VERSION 5.7 ;
  NOWIREEXTENSIONATPIN ON ;
  DIVIDERCHAR "/" ;
  BUSBITCHARS "[]" ;
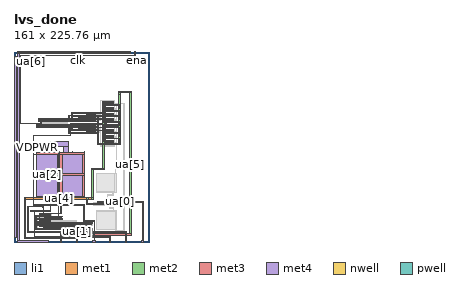
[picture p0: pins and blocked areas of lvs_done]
MACRO lvs_done (1)
  CLASS BLOCK ;
  FOREIGN lvs_done (1) ;
  ORIGIN 0.000 0.000 ;
  SIZE 161.000 BY 225.760 ;
  PIN clk
    DIRECTION INPUT ;
    USE SIGNAL ;
    ANTENNAGATEAREA 0.742500 ;
    PORT
      LAYER li1 ;
        RECT 32.645 144.295 32.980 144.565 ;
        RECT 29.625 137.870 29.955 138.120 ;
      LAYER met1 ;
        RECT 31.805 144.580 32.210 144.610 ;
        RECT 31.805 144.285 32.920 144.580 ;
        RECT 31.805 144.255 32.210 144.285 ;
        RECT 7.135 141.320 7.485 141.350 ;
        RECT 28.670 141.320 29.080 141.350 ;
        RECT 31.800 141.320 32.210 141.350 ;
        RECT 7.135 140.970 32.210 141.320 ;
        RECT 7.135 140.940 7.485 140.970 ;
        RECT 28.670 140.940 29.080 140.970 ;
        RECT 31.800 140.940 32.210 140.970 ;
        RECT 28.700 138.130 29.050 138.160 ;
        RECT 28.700 137.840 29.895 138.130 ;
        RECT 28.700 137.810 29.050 137.840 ;
      LAYER met2 ;
        RECT 7.135 221.565 7.530 221.915 ;
        RECT 7.135 141.320 7.485 221.565 ;
        RECT 31.805 144.255 32.210 144.610 ;
        RECT 31.835 141.350 32.180 144.255 ;
        RECT 7.105 140.970 7.515 141.320 ;
        RECT 28.670 140.940 29.080 141.350 ;
        RECT 31.800 140.940 32.210 141.350 ;
        RECT 28.700 137.810 29.050 140.940 ;
      LAYER met3 ;
        RECT 7.160 221.915 7.510 221.940 ;
        RECT 7.160 221.565 144.115 221.915 ;
        RECT 7.160 221.540 7.510 221.565 ;
      LAYER met4 ;
        RECT 143.740 224.710 144.190 225.765 ;
        RECT 143.740 221.560 144.090 224.710 ;
    END
  END clk
  PIN ena
    DIRECTION INPUT ;
    USE SIGNAL ;
    PORT
      LAYER met4 ;
        RECT 146.590 224.760 146.890 225.760 ;
    END
  END ena
  PIN rst_n
    DIRECTION INPUT ;
    USE SIGNAL ;
    PORT
      LAYER met4 ;
        RECT 141.070 224.760 141.370 225.760 ;
    END
  END rst_n
  PIN ua[0]
    DIRECTION INOUT ;
    USE SIGNAL ;
    ANTENNADIFFAREA 5.117500 ;
    PORT
      LAYER nwell ;
        RECT 106.360 47.870 108.640 47.900 ;
        RECT 98.640 46.280 108.640 47.870 ;
        RECT 113.030 47.890 113.870 47.910 ;
        RECT 115.230 47.890 122.970 47.910 ;
        RECT 113.030 46.305 122.970 47.890 ;
        RECT 113.040 46.300 115.470 46.305 ;
        RECT 98.640 46.265 106.380 46.280 ;
      LAYER li1 ;
        RECT 98.830 47.595 106.190 47.765 ;
        RECT 107.980 47.615 108.440 47.785 ;
        RECT 113.220 47.635 113.680 47.805 ;
        RECT 115.420 47.635 122.780 47.805 ;
        RECT 99.030 46.445 99.240 47.595 ;
        RECT 99.910 46.795 100.080 47.595 ;
        RECT 100.750 46.795 100.920 47.595 ;
        RECT 101.590 46.795 101.760 47.595 ;
        RECT 102.430 46.795 102.600 47.595 ;
        RECT 103.270 46.795 103.440 47.595 ;
        RECT 104.110 46.795 104.280 47.595 ;
        RECT 104.950 46.795 105.120 47.595 ;
        RECT 105.790 46.795 106.000 47.595 ;
        RECT 108.065 46.450 108.355 47.615 ;
        RECT 113.305 46.470 113.595 47.635 ;
        RECT 115.620 46.485 115.830 47.635 ;
        RECT 116.500 46.835 116.670 47.635 ;
        RECT 117.340 46.835 117.510 47.635 ;
        RECT 118.180 46.835 118.350 47.635 ;
        RECT 119.020 46.835 119.190 47.635 ;
        RECT 119.860 46.835 120.030 47.635 ;
        RECT 120.700 46.835 120.870 47.635 ;
        RECT 121.540 46.835 121.710 47.635 ;
        RECT 122.380 46.835 122.590 47.635 ;
      LAYER met1 ;
        RECT 98.780 47.390 153.880 48.390 ;
      LAYER met2 ;
        RECT 152.850 5.100 153.850 48.420 ;
      LAYER met3 ;
        RECT 152.825 5.285 153.875 6.285 ;
        RECT 152.850 0.010 153.850 5.285 ;
      LAYER met4 ;
        RECT 151.540 0.000 154.150 1.340 ;
    END
  END ua[0]
  PIN ua[1]
    DIRECTION INOUT ;
    USE SIGNAL ;
    ANTENNAGATEAREA 3.960000 ;
    PORT
      LAYER li1 ;
        RECT 35.975 31.975 41.415 32.215 ;
      LAYER met1 ;
        RECT 34.660 32.260 35.000 32.600 ;
        RECT 34.660 32.230 35.340 32.260 ;
        RECT 34.660 31.950 38.105 32.230 ;
        RECT 34.660 31.920 35.340 31.950 ;
      LAYER met2 ;
        RECT 16.225 42.235 16.795 42.260 ;
        RECT 16.205 41.715 16.815 42.235 ;
        RECT 16.225 12.345 16.795 41.715 ;
        RECT 33.845 41.690 35.015 42.260 ;
        RECT 34.445 41.090 35.015 41.690 ;
        RECT 34.690 32.600 34.970 41.090 ;
        RECT 34.660 32.260 35.000 32.600 ;
        RECT 34.660 31.920 35.340 32.260 ;
        RECT 16.225 11.775 16.840 12.345 ;
      LAYER met3 ;
        RECT 16.225 41.690 35.015 42.260 ;
        RECT 34.445 41.090 35.015 41.690 ;
        RECT 16.250 12.345 16.820 12.370 ;
        RECT 132.905 12.345 133.475 12.365 ;
        RECT 16.250 11.775 133.475 12.345 ;
        RECT 16.250 11.750 16.820 11.775 ;
        RECT 132.905 11.745 133.475 11.775 ;
      LAYER met4 ;
        RECT 132.900 11.770 133.480 12.340 ;
        RECT 132.905 1.240 133.475 11.770 ;
        RECT 132.390 0.000 133.570 1.240 ;
    END
  END ua[1]
  PIN ua[2]
    DIRECTION INOUT ;
    USE SIGNAL ;
    ANTENNAGATEAREA 7.920000 ;
    PORT
      LAYER li1 ;
        RECT 35.975 21.235 41.415 21.475 ;
        RECT 35.975 16.635 41.415 16.875 ;
      LAYER met1 ;
        RECT 24.375 21.520 24.715 21.860 ;
        RECT 24.375 21.490 25.055 21.520 ;
        RECT 34.320 21.490 35.340 21.520 ;
        RECT 24.375 21.210 38.105 21.490 ;
        RECT 24.375 21.180 25.055 21.210 ;
        RECT 34.320 21.180 35.340 21.210 ;
        RECT 34.660 20.840 35.000 21.180 ;
        RECT 34.660 16.920 35.000 17.260 ;
        RECT 34.660 16.890 35.340 16.920 ;
        RECT 34.660 16.610 38.105 16.890 ;
        RECT 34.660 16.580 35.340 16.610 ;
      LAYER met2 ;
        RECT 23.560 36.470 24.730 37.040 ;
        RECT 24.160 35.870 24.730 36.470 ;
        RECT 24.405 21.860 24.685 35.870 ;
        RECT 24.375 21.520 24.715 21.860 ;
        RECT 24.375 21.180 25.055 21.520 ;
        RECT 34.320 21.180 35.340 21.520 ;
        RECT 24.405 6.250 24.685 21.180 ;
        RECT 34.660 20.840 35.000 21.180 ;
        RECT 34.690 17.260 34.970 20.840 ;
        RECT 34.660 16.920 35.000 17.260 ;
        RECT 34.660 16.580 35.340 16.920 ;
        RECT 24.030 5.290 25.010 6.250 ;
      LAYER met3 ;
        RECT 42.910 37.040 43.480 37.070 ;
        RECT 20.180 36.470 43.480 37.040 ;
        RECT 24.160 35.870 24.730 36.470 ;
        RECT 42.910 36.450 43.480 36.470 ;
        RECT 24.030 6.210 25.010 6.250 ;
        RECT 113.150 6.210 114.095 6.240 ;
        RECT 24.030 5.310 114.095 6.210 ;
        RECT 24.030 5.290 25.010 5.310 ;
        RECT 113.150 5.285 114.095 5.310 ;
      LAYER met4 ;
        RECT 43.950 112.940 65.120 119.380 ;
        RECT 39.065 105.815 39.585 107.010 ;
        RECT 43.960 105.815 51.520 112.940 ;
        RECT 58.680 105.815 65.120 112.940 ;
        RECT 69.365 105.815 69.885 107.010 ;
        RECT 27.115 54.585 51.535 105.815 ;
        RECT 57.415 54.585 81.835 105.815 ;
        RECT 39.065 53.390 39.585 54.585 ;
        RECT 42.910 37.045 43.480 54.585 ;
        RECT 69.365 53.390 69.885 54.585 ;
        RECT 42.905 36.475 43.485 37.045 ;
        RECT 113.150 5.285 114.095 6.240 ;
        RECT 113.170 0.000 114.070 5.285 ;
    END
  END ua[2]
  PIN ua[3]
    DIRECTION INOUT ;
    USE SIGNAL ;
    ANTENNAGATEAREA 11.004000 ;
    ANTENNADIFFAREA 3.564000 ;
    PORT
      LAYER li1 ;
        RECT 110.350 163.915 110.605 164.245 ;
        RECT 110.350 157.355 110.605 157.685 ;
        RECT 110.350 150.795 110.605 151.125 ;
        RECT 110.350 144.235 110.605 144.565 ;
        RECT 110.350 137.295 110.605 137.625 ;
        RECT 110.350 130.735 110.605 131.065 ;
        RECT 110.350 124.175 110.605 124.505 ;
        RECT 110.350 117.615 110.605 117.945 ;
        RECT 45.480 28.985 45.810 29.785 ;
        RECT 46.320 28.985 46.650 29.785 ;
        RECT 47.160 28.985 47.490 29.785 ;
        RECT 48.000 28.985 48.330 29.785 ;
        RECT 48.840 28.985 49.170 29.785 ;
        RECT 49.680 28.985 50.010 29.785 ;
        RECT 50.520 28.985 50.850 29.785 ;
        RECT 51.360 28.985 51.690 29.785 ;
        RECT 45.480 28.815 51.690 28.985 ;
        RECT 51.360 28.225 51.690 28.815 ;
        RECT 45.480 28.035 51.690 28.225 ;
        RECT 45.480 27.575 45.810 28.035 ;
        RECT 46.320 27.575 46.650 28.035 ;
        RECT 47.160 27.575 47.490 28.035 ;
        RECT 48.000 27.575 48.330 28.035 ;
        RECT 48.840 27.575 49.170 28.035 ;
        RECT 49.680 27.575 50.010 28.035 ;
        RECT 50.520 27.575 50.850 28.035 ;
        RECT 51.360 27.575 51.690 28.035 ;
      LAYER met1 ;
        RECT 108.945 164.230 110.010 164.260 ;
        RECT 108.945 163.935 110.650 164.230 ;
        RECT 108.945 163.905 110.010 163.935 ;
        RECT 108.945 163.550 109.655 163.905 ;
        RECT 108.945 158.055 109.300 158.410 ;
        RECT 108.945 157.700 109.655 158.055 ;
        RECT 108.945 157.670 110.010 157.700 ;
        RECT 108.945 157.375 110.650 157.670 ;
        RECT 108.945 157.345 110.010 157.375 ;
        RECT 108.945 156.990 109.655 157.345 ;
        RECT 108.945 151.495 109.300 151.850 ;
        RECT 108.945 151.140 109.655 151.495 ;
        RECT 108.945 151.110 110.010 151.140 ;
        RECT 108.945 150.815 110.650 151.110 ;
        RECT 108.945 150.785 110.010 150.815 ;
        RECT 108.945 150.430 109.655 150.785 ;
        RECT 108.945 144.935 109.300 145.290 ;
        RECT 108.945 144.580 109.655 144.935 ;
        RECT 108.945 144.550 110.010 144.580 ;
        RECT 108.945 144.255 110.650 144.550 ;
        RECT 108.945 144.225 110.010 144.255 ;
        RECT 108.945 143.870 109.655 144.225 ;
        RECT 108.945 137.995 109.300 138.350 ;
        RECT 108.945 137.640 109.655 137.995 ;
        RECT 108.945 137.610 110.010 137.640 ;
        RECT 108.950 137.315 110.650 137.610 ;
        RECT 108.945 137.285 110.010 137.315 ;
        RECT 108.945 136.930 109.655 137.285 ;
        RECT 108.945 136.575 109.300 136.930 ;
        RECT 108.945 131.435 109.300 131.790 ;
        RECT 108.945 131.080 109.655 131.435 ;
        RECT 108.945 131.050 110.010 131.080 ;
        RECT 108.945 130.755 110.650 131.050 ;
        RECT 108.945 130.725 110.010 130.755 ;
        RECT 108.945 130.370 109.655 130.725 ;
        RECT 22.725 127.040 23.200 127.070 ;
        RECT 67.020 127.040 67.495 127.070 ;
        RECT 22.725 126.625 67.495 127.040 ;
        RECT 22.725 126.595 23.200 126.625 ;
        RECT 67.020 126.595 67.495 126.625 ;
        RECT 108.945 124.875 109.300 125.230 ;
        RECT 108.945 124.520 109.655 124.875 ;
        RECT 108.945 124.490 110.010 124.520 ;
        RECT 108.945 124.195 110.650 124.490 ;
        RECT 108.945 124.165 110.010 124.195 ;
        RECT 108.945 123.810 109.655 124.165 ;
        RECT 108.945 118.315 109.300 118.670 ;
        RECT 108.945 117.960 109.655 118.315 ;
        RECT 108.945 117.930 109.990 117.960 ;
        RECT 108.945 117.635 110.650 117.930 ;
        RECT 108.945 117.605 109.990 117.635 ;
        RECT 51.425 28.650 51.715 29.100 ;
        RECT 52.360 28.680 52.700 29.020 ;
        RECT 52.020 28.650 52.700 28.680 ;
        RECT 51.425 28.370 52.700 28.650 ;
        RECT 51.425 27.920 51.715 28.370 ;
        RECT 52.020 28.340 52.700 28.370 ;
      LAYER met2 ;
        RECT 108.945 163.905 110.010 164.260 ;
        RECT 108.945 163.550 109.655 163.905 ;
        RECT 108.975 158.410 109.270 163.550 ;
        RECT 108.945 158.055 109.300 158.410 ;
        RECT 108.945 157.700 109.655 158.055 ;
        RECT 108.945 157.345 110.010 157.700 ;
        RECT 108.945 156.990 109.655 157.345 ;
        RECT 108.975 151.850 109.270 156.990 ;
        RECT 108.945 151.495 109.300 151.850 ;
        RECT 108.945 151.140 109.655 151.495 ;
        RECT 108.945 150.785 110.010 151.140 ;
        RECT 108.945 150.430 109.655 150.785 ;
        RECT 108.975 145.290 109.270 150.430 ;
        RECT 108.945 144.935 109.300 145.290 ;
        RECT 108.945 144.580 109.655 144.935 ;
        RECT 108.945 144.225 110.010 144.580 ;
        RECT 108.945 143.870 109.655 144.225 ;
        RECT 108.975 141.795 109.270 143.870 ;
        RECT 67.050 127.070 67.465 141.380 ;
        RECT 108.915 140.550 109.330 141.795 ;
        RECT 108.975 138.350 109.270 140.550 ;
        RECT 108.945 137.995 109.300 138.350 ;
        RECT 108.945 137.640 109.655 137.995 ;
        RECT 108.945 137.285 110.010 137.640 ;
        RECT 108.945 136.930 109.655 137.285 ;
        RECT 108.945 136.575 109.300 136.930 ;
        RECT 108.975 131.790 109.270 136.575 ;
        RECT 108.945 131.435 109.300 131.790 ;
        RECT 108.945 131.080 109.655 131.435 ;
        RECT 108.945 130.725 110.010 131.080 ;
        RECT 108.945 130.370 109.655 130.725 ;
        RECT 22.725 126.595 23.200 127.070 ;
        RECT 67.020 126.595 67.495 127.070 ;
        RECT 22.755 44.020 23.170 126.595 ;
        RECT 108.975 125.230 109.270 130.370 ;
        RECT 108.945 124.875 109.300 125.230 ;
        RECT 108.945 124.520 109.655 124.875 ;
        RECT 108.945 124.165 110.010 124.520 ;
        RECT 108.945 123.810 109.655 124.165 ;
        RECT 108.975 118.880 109.270 123.810 ;
        RECT 108.945 118.865 109.270 118.880 ;
        RECT 108.945 118.315 109.300 118.865 ;
        RECT 108.945 117.960 109.655 118.315 ;
        RECT 108.945 117.605 109.990 117.960 ;
        RECT 22.720 43.410 23.335 44.020 ;
        RECT 51.545 43.430 52.715 44.000 ;
        RECT 83.025 43.975 83.595 44.000 ;
        RECT 83.005 43.455 83.615 43.975 ;
        RECT 52.145 42.830 52.715 43.430 ;
        RECT 52.390 29.020 52.670 42.830 ;
        RECT 52.360 28.680 52.700 29.020 ;
        RECT 52.020 28.340 52.700 28.680 ;
        RECT 83.025 24.880 83.595 43.455 ;
      LAYER met3 ;
        RECT 108.915 141.380 109.330 141.795 ;
        RECT 67.050 140.965 109.330 141.380 ;
        RECT 108.915 140.550 109.330 140.965 ;
        RECT 26.720 106.195 53.690 106.210 ;
        RECT 57.020 106.195 83.990 106.210 ;
        RECT 22.730 104.515 23.195 105.205 ;
        RECT 26.720 104.515 83.990 106.195 ;
        RECT 22.730 104.100 83.990 104.515 ;
        RECT 22.730 103.280 23.195 104.100 ;
        RECT 26.720 81.000 83.990 104.100 ;
        RECT 26.720 79.400 83.985 81.000 ;
        RECT 26.720 54.190 83.990 79.400 ;
        RECT 26.720 54.180 83.985 54.190 ;
        RECT 22.720 44.000 23.335 44.020 ;
        RECT 22.720 43.430 83.595 44.000 ;
        RECT 22.720 43.410 23.335 43.430 ;
        RECT 52.145 42.830 52.715 43.430 ;
        RECT 95.605 25.470 96.175 25.490 ;
        RECT 83.000 24.900 96.175 25.470 ;
        RECT 95.605 24.870 96.175 24.900 ;
      LAYER met4 ;
        RECT 53.170 53.390 53.690 107.010 ;
        RECT 83.470 53.390 83.990 107.010 ;
        RECT 95.600 24.895 96.180 25.465 ;
        RECT 95.605 1.220 96.175 24.895 ;
        RECT 93.850 0.000 96.340 1.220 ;
        RECT 95.605 -0.005 96.175 0.000 ;
    END
  END ua[3]
  PIN ua[4]
    DIRECTION INOUT ;
    USE SIGNAL ;
    ANTENNADIFFAREA 94.840645 ;
    PORT
      LAYER nwell ;
        RECT 107.805 164.225 118.730 165.830 ;
        RECT 107.715 157.665 118.730 159.270 ;
        RECT 85.660 151.825 97.320 153.430 ;
        RECT 107.715 151.105 118.730 152.710 ;
        RECT 76.650 148.185 97.320 149.790 ;
        RECT 28.850 144.545 97.320 146.150 ;
        RECT 108.120 146.145 118.730 146.150 ;
        RECT 107.820 144.545 118.730 146.145 ;
        RECT 66.485 144.535 67.325 144.545 ;
        RECT 107.820 144.540 108.660 144.545 ;
        RECT 26.975 138.100 97.320 139.705 ;
        RECT 110.070 137.605 123.260 139.210 ;
        RECT 76.650 134.460 97.320 136.065 ;
        RECT 85.660 132.415 86.500 132.420 ;
        RECT 85.660 130.815 97.320 132.415 ;
        RECT 107.695 131.045 118.730 132.650 ;
        RECT 86.320 130.810 97.320 130.815 ;
        RECT 108.090 124.485 118.730 126.090 ;
        RECT 107.620 117.925 118.730 119.530 ;
      LAYER pwell ;
        RECT 107.995 45.170 108.425 45.955 ;
        RECT 113.235 45.190 113.665 45.975 ;
      LAYER nwell ;
        RECT 31.485 32.205 43.440 33.810 ;
        RECT 35.700 28.625 56.750 30.230 ;
        RECT 31.875 25.045 43.440 26.650 ;
        RECT 35.700 21.465 72.580 23.070 ;
        RECT 73.850 21.465 92.710 23.070 ;
        RECT 80.715 18.470 83.700 18.475 ;
        RECT 35.700 16.865 72.580 18.470 ;
        RECT 73.850 16.870 83.700 18.470 ;
        RECT 73.850 16.865 81.835 16.870 ;
      LAYER li1 ;
        RECT 107.995 165.555 108.455 165.725 ;
        RECT 110.260 165.555 118.540 165.725 ;
        RECT 108.080 164.390 108.370 165.555 ;
        RECT 110.775 164.755 111.105 165.555 ;
        RECT 111.670 164.755 112.000 165.555 ;
        RECT 112.510 164.755 112.840 165.555 ;
        RECT 113.350 164.755 113.680 165.555 ;
        RECT 114.190 164.755 114.540 165.555 ;
        RECT 107.905 158.995 108.365 159.165 ;
        RECT 110.260 158.995 118.540 159.165 ;
        RECT 107.990 157.830 108.280 158.995 ;
        RECT 110.775 158.195 111.105 158.995 ;
        RECT 111.670 158.195 112.000 158.995 ;
        RECT 112.510 158.195 112.840 158.995 ;
        RECT 113.350 158.195 113.680 158.995 ;
        RECT 114.190 158.195 114.540 158.995 ;
        RECT 85.850 153.155 86.310 153.325 ;
        RECT 89.770 153.155 97.130 153.325 ;
        RECT 85.935 151.990 86.225 153.155 ;
        RECT 89.970 152.005 90.180 153.155 ;
        RECT 90.850 152.355 91.020 153.155 ;
        RECT 91.690 152.355 91.860 153.155 ;
        RECT 92.530 152.355 92.700 153.155 ;
        RECT 93.370 152.355 93.540 153.155 ;
        RECT 94.210 152.355 94.380 153.155 ;
        RECT 95.050 152.355 95.220 153.155 ;
        RECT 95.890 152.355 96.060 153.155 ;
        RECT 96.730 152.355 96.940 153.155 ;
        RECT 107.905 152.435 108.365 152.605 ;
        RECT 110.260 152.435 118.540 152.605 ;
        RECT 107.990 151.270 108.280 152.435 ;
        RECT 110.775 151.635 111.105 152.435 ;
        RECT 111.670 151.635 112.000 152.435 ;
        RECT 112.510 151.635 112.840 152.435 ;
        RECT 113.350 151.635 113.680 152.435 ;
        RECT 114.190 151.635 114.540 152.435 ;
        RECT 76.840 149.515 77.300 149.685 ;
        RECT 78.950 149.515 86.310 149.685 ;
        RECT 89.770 149.515 97.130 149.685 ;
        RECT 76.925 148.350 77.215 149.515 ;
        RECT 79.150 148.365 79.360 149.515 ;
        RECT 80.030 148.715 80.200 149.515 ;
        RECT 80.870 148.715 81.040 149.515 ;
        RECT 81.710 148.715 81.880 149.515 ;
        RECT 82.550 148.715 82.720 149.515 ;
        RECT 83.390 148.715 83.560 149.515 ;
        RECT 84.230 148.715 84.400 149.515 ;
        RECT 85.070 148.715 85.240 149.515 ;
        RECT 85.910 148.715 86.120 149.515 ;
        RECT 89.970 148.365 90.180 149.515 ;
        RECT 90.850 148.715 91.020 149.515 ;
        RECT 91.690 148.715 91.860 149.515 ;
        RECT 92.530 148.715 92.700 149.515 ;
        RECT 93.370 148.715 93.540 149.515 ;
        RECT 94.210 148.715 94.380 149.515 ;
        RECT 95.050 148.715 95.220 149.515 ;
        RECT 95.890 148.715 96.060 149.515 ;
        RECT 96.730 148.715 96.940 149.515 ;
        RECT 29.040 145.875 29.500 146.045 ;
        RECT 32.550 145.875 33.930 146.045 ;
        RECT 35.585 145.875 36.965 146.045 ;
        RECT 38.615 145.875 39.995 146.045 ;
        RECT 41.645 145.875 43.025 146.045 ;
        RECT 44.675 145.875 46.975 146.045 ;
        RECT 48.630 145.875 52.770 146.045 ;
        RECT 54.420 145.875 60.400 146.045 ;
        RECT 29.125 144.710 29.415 145.875 ;
        RECT 32.635 144.735 32.915 145.875 ;
        RECT 33.585 144.735 33.845 145.875 ;
        RECT 35.925 144.735 36.135 145.875 ;
        RECT 38.955 144.735 39.165 145.875 ;
        RECT 41.770 144.735 42.000 145.875 ;
        RECT 42.670 144.735 42.880 145.875 ;
        RECT 44.805 144.735 45.070 145.875 ;
        RECT 45.740 145.075 45.910 145.875 ;
        RECT 46.580 145.415 46.790 145.875 ;
        RECT 48.885 145.075 49.140 145.875 ;
        RECT 49.810 145.075 49.980 145.875 ;
        RECT 50.650 145.075 50.820 145.875 ;
        RECT 51.490 145.075 51.660 145.875 ;
        RECT 52.330 145.075 52.630 145.875 ;
        RECT 54.675 145.075 54.930 145.875 ;
        RECT 55.600 145.075 55.770 145.875 ;
        RECT 56.440 145.075 56.610 145.875 ;
        RECT 57.280 145.075 57.450 145.875 ;
        RECT 58.120 145.075 58.290 145.875 ;
        RECT 58.960 145.075 59.130 145.875 ;
        RECT 59.975 145.075 60.315 145.875 ;
        RECT 66.675 145.865 67.135 146.035 ;
        RECT 69.940 145.875 77.300 146.045 ;
        RECT 78.950 145.875 86.310 146.045 ;
        RECT 87.895 145.875 88.355 146.045 ;
        RECT 89.770 145.875 97.130 146.045 ;
        RECT 66.760 144.700 67.050 145.865 ;
        RECT 70.140 144.725 70.350 145.875 ;
        RECT 71.020 145.075 71.190 145.875 ;
        RECT 71.860 145.075 72.030 145.875 ;
        RECT 72.700 145.075 72.870 145.875 ;
        RECT 73.540 145.075 73.710 145.875 ;
        RECT 74.380 145.075 74.550 145.875 ;
        RECT 75.220 145.075 75.390 145.875 ;
        RECT 76.060 145.075 76.230 145.875 ;
        RECT 76.900 145.075 77.110 145.875 ;
        RECT 79.150 144.725 79.360 145.875 ;
        RECT 80.030 145.075 80.200 145.875 ;
        RECT 80.870 145.075 81.040 145.875 ;
        RECT 81.710 145.075 81.880 145.875 ;
        RECT 82.550 145.075 82.720 145.875 ;
        RECT 83.390 145.075 83.560 145.875 ;
        RECT 84.230 145.075 84.400 145.875 ;
        RECT 85.070 145.075 85.240 145.875 ;
        RECT 85.910 145.075 86.120 145.875 ;
        RECT 87.980 144.710 88.270 145.875 ;
        RECT 89.970 144.725 90.180 145.875 ;
        RECT 90.850 145.075 91.020 145.875 ;
        RECT 91.690 145.075 91.860 145.875 ;
        RECT 92.530 145.075 92.700 145.875 ;
        RECT 93.370 145.075 93.540 145.875 ;
        RECT 94.210 145.075 94.380 145.875 ;
        RECT 95.050 145.075 95.220 145.875 ;
        RECT 95.890 145.075 96.060 145.875 ;
        RECT 96.730 145.075 96.940 145.875 ;
        RECT 108.010 145.870 108.470 146.040 ;
        RECT 110.260 145.875 118.540 146.045 ;
        RECT 108.095 144.705 108.385 145.870 ;
        RECT 110.775 145.075 111.105 145.875 ;
        RECT 111.670 145.075 112.000 145.875 ;
        RECT 112.510 145.075 112.840 145.875 ;
        RECT 113.350 145.075 113.680 145.875 ;
        RECT 114.190 145.075 114.540 145.875 ;
        RECT 27.165 139.430 27.625 139.600 ;
        RECT 29.520 139.430 30.900 139.600 ;
        RECT 32.550 139.430 33.930 139.600 ;
        RECT 35.580 139.430 36.960 139.600 ;
        RECT 38.610 139.430 39.990 139.600 ;
        RECT 41.640 139.430 43.020 139.600 ;
        RECT 44.670 139.430 46.970 139.600 ;
        RECT 48.620 139.430 52.760 139.600 ;
        RECT 54.410 139.430 60.390 139.600 ;
        RECT 63.365 139.430 63.825 139.600 ;
        RECT 69.940 139.430 77.300 139.600 ;
        RECT 78.950 139.430 86.310 139.600 ;
        RECT 87.895 139.430 88.355 139.600 ;
        RECT 89.770 139.430 97.130 139.600 ;
        RECT 27.250 138.265 27.540 139.430 ;
        RECT 29.645 138.290 29.875 139.430 ;
        RECT 30.545 138.290 30.755 139.430 ;
        RECT 32.635 138.290 32.915 139.430 ;
        RECT 33.585 138.290 33.845 139.430 ;
        RECT 35.920 138.290 36.130 139.430 ;
        RECT 38.950 138.290 39.160 139.430 ;
        RECT 41.765 138.290 41.995 139.430 ;
        RECT 42.665 138.290 42.875 139.430 ;
        RECT 44.800 138.290 45.065 139.430 ;
        RECT 45.735 138.630 45.905 139.430 ;
        RECT 46.575 138.970 46.785 139.430 ;
        RECT 48.875 138.630 49.130 139.430 ;
        RECT 49.800 138.630 49.970 139.430 ;
        RECT 50.640 138.630 50.810 139.430 ;
        RECT 51.480 138.630 51.650 139.430 ;
        RECT 52.320 138.630 52.620 139.430 ;
        RECT 54.665 138.630 54.920 139.430 ;
        RECT 55.590 138.630 55.760 139.430 ;
        RECT 56.430 138.630 56.600 139.430 ;
        RECT 57.270 138.630 57.440 139.430 ;
        RECT 58.110 138.630 58.280 139.430 ;
        RECT 58.950 138.630 59.120 139.430 ;
        RECT 59.965 138.630 60.305 139.430 ;
        RECT 63.450 138.265 63.740 139.430 ;
        RECT 70.140 138.280 70.350 139.430 ;
        RECT 71.020 138.630 71.190 139.430 ;
        RECT 71.860 138.630 72.030 139.430 ;
        RECT 72.700 138.630 72.870 139.430 ;
        RECT 73.540 138.630 73.710 139.430 ;
        RECT 74.380 138.630 74.550 139.430 ;
        RECT 75.220 138.630 75.390 139.430 ;
        RECT 76.060 138.630 76.230 139.430 ;
        RECT 76.900 138.630 77.110 139.430 ;
        RECT 79.150 138.280 79.360 139.430 ;
        RECT 80.030 138.630 80.200 139.430 ;
        RECT 80.870 138.630 81.040 139.430 ;
        RECT 81.710 138.630 81.880 139.430 ;
        RECT 82.550 138.630 82.720 139.430 ;
        RECT 83.390 138.630 83.560 139.430 ;
        RECT 84.230 138.630 84.400 139.430 ;
        RECT 85.070 138.630 85.240 139.430 ;
        RECT 85.910 138.630 86.120 139.430 ;
        RECT 87.980 138.265 88.270 139.430 ;
        RECT 89.970 138.280 90.180 139.430 ;
        RECT 90.850 138.630 91.020 139.430 ;
        RECT 91.690 138.630 91.860 139.430 ;
        RECT 92.530 138.630 92.700 139.430 ;
        RECT 93.370 138.630 93.540 139.430 ;
        RECT 94.210 138.630 94.380 139.430 ;
        RECT 95.050 138.630 95.220 139.430 ;
        RECT 95.890 138.630 96.060 139.430 ;
        RECT 96.730 138.630 96.940 139.430 ;
        RECT 110.260 138.935 118.540 139.105 ;
        RECT 122.610 138.935 123.070 139.105 ;
        RECT 110.775 138.135 111.105 138.935 ;
        RECT 111.670 138.135 112.000 138.935 ;
        RECT 112.510 138.135 112.840 138.935 ;
        RECT 113.350 138.135 113.680 138.935 ;
        RECT 114.190 138.135 114.540 138.935 ;
        RECT 122.695 137.770 122.985 138.935 ;
        RECT 76.840 135.790 77.300 135.960 ;
        RECT 78.950 135.790 86.310 135.960 ;
        RECT 89.770 135.790 97.130 135.960 ;
        RECT 76.925 134.625 77.215 135.790 ;
        RECT 79.150 134.640 79.360 135.790 ;
        RECT 80.030 134.990 80.200 135.790 ;
        RECT 80.870 134.990 81.040 135.790 ;
        RECT 81.710 134.990 81.880 135.790 ;
        RECT 82.550 134.990 82.720 135.790 ;
        RECT 83.390 134.990 83.560 135.790 ;
        RECT 84.230 134.990 84.400 135.790 ;
        RECT 85.070 134.990 85.240 135.790 ;
        RECT 85.910 134.990 86.120 135.790 ;
        RECT 89.970 134.640 90.180 135.790 ;
        RECT 90.850 134.990 91.020 135.790 ;
        RECT 91.690 134.990 91.860 135.790 ;
        RECT 92.530 134.990 92.700 135.790 ;
        RECT 93.370 134.990 93.540 135.790 ;
        RECT 94.210 134.990 94.380 135.790 ;
        RECT 95.050 134.990 95.220 135.790 ;
        RECT 95.890 134.990 96.060 135.790 ;
        RECT 96.730 134.990 96.940 135.790 ;
        RECT 107.885 132.375 108.345 132.545 ;
        RECT 110.260 132.375 118.540 132.545 ;
        RECT 85.850 132.145 86.310 132.315 ;
        RECT 85.935 130.980 86.225 132.145 ;
        RECT 89.770 132.140 97.130 132.310 ;
        RECT 89.970 130.990 90.180 132.140 ;
        RECT 90.850 131.340 91.020 132.140 ;
        RECT 91.690 131.340 91.860 132.140 ;
        RECT 92.530 131.340 92.700 132.140 ;
        RECT 93.370 131.340 93.540 132.140 ;
        RECT 94.210 131.340 94.380 132.140 ;
        RECT 95.050 131.340 95.220 132.140 ;
        RECT 95.890 131.340 96.060 132.140 ;
        RECT 96.730 131.340 96.940 132.140 ;
        RECT 107.970 131.210 108.260 132.375 ;
        RECT 110.775 131.575 111.105 132.375 ;
        RECT 111.670 131.575 112.000 132.375 ;
        RECT 112.510 131.575 112.840 132.375 ;
        RECT 113.350 131.575 113.680 132.375 ;
        RECT 114.190 131.575 114.540 132.375 ;
        RECT 108.280 125.815 108.740 125.985 ;
        RECT 110.260 125.815 118.540 125.985 ;
        RECT 108.365 124.650 108.655 125.815 ;
        RECT 110.775 125.015 111.105 125.815 ;
        RECT 111.670 125.015 112.000 125.815 ;
        RECT 112.510 125.015 112.840 125.815 ;
        RECT 113.350 125.015 113.680 125.815 ;
        RECT 114.190 125.015 114.540 125.815 ;
        RECT 107.810 119.255 108.270 119.425 ;
        RECT 110.260 119.255 118.540 119.425 ;
        RECT 107.895 118.090 108.185 119.255 ;
        RECT 110.775 118.455 111.105 119.255 ;
        RECT 111.670 118.455 112.000 119.255 ;
        RECT 112.510 118.455 112.840 119.255 ;
        RECT 113.350 118.455 113.680 119.255 ;
        RECT 114.190 118.455 114.540 119.255 ;
        RECT 99.010 45.045 99.240 45.845 ;
        RECT 99.910 45.045 100.080 45.505 ;
        RECT 100.750 45.045 100.920 45.505 ;
        RECT 101.590 45.045 101.760 45.505 ;
        RECT 102.430 45.045 102.600 45.505 ;
        RECT 103.270 45.045 103.440 45.505 ;
        RECT 104.110 45.045 104.280 45.505 ;
        RECT 104.950 45.045 105.120 45.505 ;
        RECT 105.790 45.045 106.000 45.845 ;
        RECT 108.065 45.065 108.355 45.790 ;
        RECT 113.305 45.085 113.595 45.810 ;
        RECT 115.600 45.085 115.830 45.885 ;
        RECT 116.500 45.085 116.670 45.545 ;
        RECT 117.340 45.085 117.510 45.545 ;
        RECT 118.180 45.085 118.350 45.545 ;
        RECT 119.020 45.085 119.190 45.545 ;
        RECT 119.860 45.085 120.030 45.545 ;
        RECT 120.700 45.085 120.870 45.545 ;
        RECT 121.540 45.085 121.710 45.545 ;
        RECT 122.380 45.085 122.590 45.885 ;
        RECT 98.830 44.875 106.190 45.045 ;
        RECT 107.980 44.895 108.440 45.065 ;
        RECT 113.220 44.915 113.680 45.085 ;
        RECT 115.420 44.915 122.780 45.085 ;
        RECT 31.675 33.535 32.135 33.705 ;
        RECT 35.890 33.535 43.250 33.705 ;
        RECT 31.760 32.370 32.050 33.535 ;
        RECT 36.090 32.385 36.300 33.535 ;
        RECT 36.970 32.735 37.140 33.535 ;
        RECT 37.810 32.735 37.980 33.535 ;
        RECT 38.650 32.735 38.820 33.535 ;
        RECT 39.490 32.735 39.660 33.535 ;
        RECT 40.330 32.735 40.500 33.535 ;
        RECT 41.170 32.735 41.340 33.535 ;
        RECT 42.010 32.735 42.180 33.535 ;
        RECT 42.850 32.735 43.060 33.535 ;
        RECT 35.890 29.955 43.250 30.125 ;
        RECT 44.900 29.955 52.260 30.125 ;
        RECT 56.100 29.955 56.560 30.125 ;
        RECT 36.090 28.805 36.300 29.955 ;
        RECT 36.970 29.155 37.140 29.955 ;
        RECT 37.810 29.155 37.980 29.955 ;
        RECT 38.650 29.155 38.820 29.955 ;
        RECT 39.490 29.155 39.660 29.955 ;
        RECT 40.330 29.155 40.500 29.955 ;
        RECT 41.170 29.155 41.340 29.955 ;
        RECT 42.010 29.155 42.180 29.955 ;
        RECT 42.850 29.155 43.060 29.955 ;
        RECT 45.100 28.805 45.310 29.955 ;
        RECT 45.980 29.155 46.150 29.955 ;
        RECT 46.820 29.155 46.990 29.955 ;
        RECT 47.660 29.155 47.830 29.955 ;
        RECT 48.500 29.155 48.670 29.955 ;
        RECT 49.340 29.155 49.510 29.955 ;
        RECT 50.180 29.155 50.350 29.955 ;
        RECT 51.020 29.155 51.190 29.955 ;
        RECT 51.860 29.155 52.070 29.955 ;
        RECT 56.185 28.790 56.475 29.955 ;
        RECT 32.065 26.375 32.525 26.545 ;
        RECT 35.890 26.375 43.250 26.545 ;
        RECT 32.150 25.210 32.440 26.375 ;
        RECT 36.090 25.225 36.300 26.375 ;
        RECT 36.970 25.575 37.140 26.375 ;
        RECT 37.810 25.575 37.980 26.375 ;
        RECT 38.650 25.575 38.820 26.375 ;
        RECT 39.490 25.575 39.660 26.375 ;
        RECT 40.330 25.575 40.500 26.375 ;
        RECT 41.170 25.575 41.340 26.375 ;
        RECT 42.010 25.575 42.180 26.375 ;
        RECT 42.850 25.575 43.060 26.375 ;
        RECT 35.890 22.795 43.250 22.965 ;
        RECT 44.900 22.795 52.260 22.965 ;
        RECT 53.910 22.795 54.370 22.965 ;
        RECT 56.020 22.795 63.380 22.965 ;
        RECT 65.030 22.795 72.390 22.965 ;
        RECT 74.040 22.795 81.400 22.965 ;
        RECT 83.050 22.795 83.510 22.965 ;
        RECT 85.160 22.795 92.520 22.965 ;
        RECT 36.090 21.645 36.300 22.795 ;
        RECT 36.970 21.995 37.140 22.795 ;
        RECT 37.810 21.995 37.980 22.795 ;
        RECT 38.650 21.995 38.820 22.795 ;
        RECT 39.490 21.995 39.660 22.795 ;
        RECT 40.330 21.995 40.500 22.795 ;
        RECT 41.170 21.995 41.340 22.795 ;
        RECT 42.010 21.995 42.180 22.795 ;
        RECT 42.850 21.995 43.060 22.795 ;
        RECT 45.100 21.645 45.310 22.795 ;
        RECT 45.980 21.995 46.150 22.795 ;
        RECT 46.820 21.995 46.990 22.795 ;
        RECT 47.660 21.995 47.830 22.795 ;
        RECT 48.500 21.995 48.670 22.795 ;
        RECT 49.340 21.995 49.510 22.795 ;
        RECT 50.180 21.995 50.350 22.795 ;
        RECT 51.020 21.995 51.190 22.795 ;
        RECT 51.860 21.995 52.070 22.795 ;
        RECT 53.995 21.630 54.285 22.795 ;
        RECT 56.220 21.645 56.430 22.795 ;
        RECT 57.100 21.995 57.270 22.795 ;
        RECT 57.940 21.995 58.110 22.795 ;
        RECT 58.780 21.995 58.950 22.795 ;
        RECT 59.620 21.995 59.790 22.795 ;
        RECT 60.460 21.995 60.630 22.795 ;
        RECT 61.300 21.995 61.470 22.795 ;
        RECT 62.140 21.995 62.310 22.795 ;
        RECT 62.980 21.995 63.190 22.795 ;
        RECT 65.230 21.645 65.440 22.795 ;
        RECT 66.110 21.995 66.280 22.795 ;
        RECT 66.950 21.995 67.120 22.795 ;
        RECT 67.790 21.995 67.960 22.795 ;
        RECT 68.630 21.995 68.800 22.795 ;
        RECT 69.470 21.995 69.640 22.795 ;
        RECT 70.310 21.995 70.480 22.795 ;
        RECT 71.150 21.995 71.320 22.795 ;
        RECT 71.990 21.995 72.200 22.795 ;
        RECT 74.240 21.645 74.450 22.795 ;
        RECT 75.120 21.995 75.290 22.795 ;
        RECT 75.960 21.995 76.130 22.795 ;
        RECT 76.800 21.995 76.970 22.795 ;
        RECT 77.640 21.995 77.810 22.795 ;
        RECT 78.480 21.995 78.650 22.795 ;
        RECT 79.320 21.995 79.490 22.795 ;
        RECT 80.160 21.995 80.330 22.795 ;
        RECT 81.000 21.995 81.210 22.795 ;
        RECT 83.135 21.630 83.425 22.795 ;
        RECT 85.360 21.645 85.570 22.795 ;
        RECT 86.240 21.995 86.410 22.795 ;
        RECT 87.080 21.995 87.250 22.795 ;
        RECT 87.920 21.995 88.090 22.795 ;
        RECT 88.760 21.995 88.930 22.795 ;
        RECT 89.600 21.995 89.770 22.795 ;
        RECT 90.440 21.995 90.610 22.795 ;
        RECT 91.280 21.995 91.450 22.795 ;
        RECT 92.120 21.995 92.330 22.795 ;
        RECT 35.890 18.195 43.250 18.365 ;
        RECT 44.900 18.195 52.260 18.365 ;
        RECT 53.910 18.195 54.370 18.365 ;
        RECT 56.020 18.195 63.380 18.365 ;
        RECT 65.030 18.195 72.390 18.365 ;
        RECT 74.040 18.195 81.400 18.365 ;
        RECT 83.050 18.200 83.510 18.370 ;
        RECT 36.090 17.045 36.300 18.195 ;
        RECT 36.970 17.395 37.140 18.195 ;
        RECT 37.810 17.395 37.980 18.195 ;
        RECT 38.650 17.395 38.820 18.195 ;
        RECT 39.490 17.395 39.660 18.195 ;
        RECT 40.330 17.395 40.500 18.195 ;
        RECT 41.170 17.395 41.340 18.195 ;
        RECT 42.010 17.395 42.180 18.195 ;
        RECT 42.850 17.395 43.060 18.195 ;
        RECT 45.100 17.045 45.310 18.195 ;
        RECT 45.980 17.395 46.150 18.195 ;
        RECT 46.820 17.395 46.990 18.195 ;
        RECT 47.660 17.395 47.830 18.195 ;
        RECT 48.500 17.395 48.670 18.195 ;
        RECT 49.340 17.395 49.510 18.195 ;
        RECT 50.180 17.395 50.350 18.195 ;
        RECT 51.020 17.395 51.190 18.195 ;
        RECT 51.860 17.395 52.070 18.195 ;
        RECT 53.995 17.030 54.285 18.195 ;
        RECT 56.220 17.045 56.430 18.195 ;
        RECT 57.100 17.395 57.270 18.195 ;
        RECT 57.940 17.395 58.110 18.195 ;
        RECT 58.780 17.395 58.950 18.195 ;
        RECT 59.620 17.395 59.790 18.195 ;
        RECT 60.460 17.395 60.630 18.195 ;
        RECT 61.300 17.395 61.470 18.195 ;
        RECT 62.140 17.395 62.310 18.195 ;
        RECT 62.980 17.395 63.190 18.195 ;
        RECT 65.230 17.045 65.440 18.195 ;
        RECT 66.110 17.395 66.280 18.195 ;
        RECT 66.950 17.395 67.120 18.195 ;
        RECT 67.790 17.395 67.960 18.195 ;
        RECT 68.630 17.395 68.800 18.195 ;
        RECT 69.470 17.395 69.640 18.195 ;
        RECT 70.310 17.395 70.480 18.195 ;
        RECT 71.150 17.395 71.320 18.195 ;
        RECT 71.990 17.395 72.200 18.195 ;
        RECT 74.240 17.045 74.450 18.195 ;
        RECT 75.120 17.395 75.290 18.195 ;
        RECT 75.960 17.395 76.130 18.195 ;
        RECT 76.800 17.395 76.970 18.195 ;
        RECT 77.640 17.395 77.810 18.195 ;
        RECT 78.480 17.395 78.650 18.195 ;
        RECT 79.320 17.395 79.490 18.195 ;
        RECT 80.160 17.395 80.330 18.195 ;
        RECT 81.000 17.395 81.210 18.195 ;
        RECT 83.135 17.035 83.425 18.200 ;
      LAYER met1 ;
        RECT 105.190 166.360 107.230 166.395 ;
        RECT 105.190 165.880 118.115 166.360 ;
        RECT 105.190 165.400 118.540 165.880 ;
        RECT 105.190 165.370 107.230 165.400 ;
        RECT 105.220 164.345 107.200 165.370 ;
        RECT 105.190 163.320 107.230 164.345 ;
        RECT 105.220 162.295 107.200 163.320 ;
        RECT 105.190 161.270 107.230 162.295 ;
        RECT 105.220 159.835 107.200 161.270 ;
        RECT 105.190 159.800 107.230 159.835 ;
        RECT 105.190 159.320 118.115 159.800 ;
        RECT 105.190 158.840 118.540 159.320 ;
        RECT 105.190 158.810 107.230 158.840 ;
        RECT 105.220 157.785 107.200 158.810 ;
        RECT 105.190 156.760 107.230 157.785 ;
        RECT 105.220 155.325 107.200 156.760 ;
        RECT 105.190 154.300 107.230 155.325 ;
        RECT 68.480 153.480 69.020 153.510 ;
        RECT 105.220 153.480 107.200 154.300 ;
        RECT 68.480 153.275 107.200 153.480 ;
        RECT 68.480 153.240 107.230 153.275 ;
        RECT 68.480 153.000 118.115 153.240 ;
        RECT 68.480 152.970 69.020 153.000 ;
        RECT 105.190 152.760 118.115 153.000 ;
        RECT 105.190 152.280 118.540 152.760 ;
        RECT 105.190 152.250 107.230 152.280 ;
        RECT 105.220 151.225 107.200 152.250 ;
        RECT 105.190 150.200 107.230 151.225 ;
        RECT 68.480 149.840 69.020 149.870 ;
        RECT 105.220 149.840 107.200 150.200 ;
        RECT 68.480 149.360 107.200 149.840 ;
        RECT 68.480 149.330 69.020 149.360 ;
        RECT 105.220 149.175 107.200 149.360 ;
        RECT 105.190 148.150 107.230 149.175 ;
        RECT 105.220 146.715 107.200 148.150 ;
        RECT 105.190 146.680 107.230 146.715 ;
        RECT 68.480 146.200 69.020 146.230 ;
        RECT 105.190 146.200 118.115 146.680 ;
        RECT 29.040 145.720 118.540 146.200 ;
        RECT 66.675 145.710 67.135 145.720 ;
        RECT 68.480 145.690 69.020 145.720 ;
        RECT 105.190 145.690 107.230 145.720 ;
        RECT 108.010 145.715 108.470 145.720 ;
        RECT 105.220 144.665 107.200 145.690 ;
        RECT 105.190 143.640 107.230 144.665 ;
        RECT 105.220 142.615 107.200 143.640 ;
        RECT 105.190 141.590 107.230 142.615 ;
        RECT 68.480 139.755 69.020 139.785 ;
        RECT 105.220 139.775 107.200 141.590 ;
        RECT 105.190 139.755 107.230 139.775 ;
        RECT 27.165 139.275 123.065 139.755 ;
        RECT 31.915 139.270 32.205 139.275 ;
        RECT 68.480 139.245 69.020 139.275 ;
        RECT 105.190 139.260 123.065 139.275 ;
        RECT 105.190 138.780 123.070 139.260 ;
        RECT 105.190 138.750 107.230 138.780 ;
        RECT 105.220 137.725 107.200 138.750 ;
        RECT 105.190 136.700 107.230 137.725 ;
        RECT 68.480 136.115 69.020 136.145 ;
        RECT 105.220 136.115 107.200 136.700 ;
        RECT 68.480 135.675 107.200 136.115 ;
        RECT 68.480 135.635 107.230 135.675 ;
        RECT 68.480 135.605 69.020 135.635 ;
        RECT 105.190 134.650 107.230 135.635 ;
        RECT 105.220 133.215 107.200 134.650 ;
        RECT 105.190 133.180 107.230 133.215 ;
        RECT 68.480 132.465 69.020 132.505 ;
        RECT 85.850 132.465 86.310 132.470 ;
        RECT 86.880 132.465 87.260 132.475 ;
        RECT 105.190 132.465 118.540 133.180 ;
        RECT 68.480 132.220 118.540 132.465 ;
        RECT 68.480 132.190 107.230 132.220 ;
        RECT 68.480 131.995 107.200 132.190 ;
        RECT 68.480 131.965 69.020 131.995 ;
        RECT 85.850 131.990 86.310 131.995 ;
        RECT 89.770 131.985 97.130 131.995 ;
        RECT 105.220 131.165 107.200 131.995 ;
        RECT 105.190 130.140 107.230 131.165 ;
        RECT 105.220 129.115 107.200 130.140 ;
        RECT 105.190 128.090 107.230 129.115 ;
        RECT 105.220 126.655 107.200 128.090 ;
        RECT 105.190 126.620 107.230 126.655 ;
        RECT 105.190 125.660 118.540 126.620 ;
        RECT 105.190 125.630 107.230 125.660 ;
        RECT 105.220 124.605 107.200 125.630 ;
        RECT 105.190 123.580 107.230 124.605 ;
        RECT 105.220 122.555 107.200 123.580 ;
        RECT 105.195 121.530 107.235 122.555 ;
        RECT 105.220 120.095 107.200 121.530 ;
        RECT 105.190 120.060 107.230 120.095 ;
        RECT 105.190 119.100 118.540 120.060 ;
        RECT 105.190 119.070 107.230 119.100 ;
        RECT 92.595 87.750 94.615 87.780 ;
        RECT 105.190 87.750 107.210 87.780 ;
        RECT 92.595 85.790 107.210 87.750 ;
        RECT 92.595 85.760 94.615 85.790 ;
        RECT 105.190 85.760 107.210 85.790 ;
        RECT 55.460 52.735 57.480 52.765 ;
        RECT 86.350 52.735 88.370 52.765 ;
        RECT 92.595 52.735 94.615 52.765 ;
        RECT 12.020 50.775 94.615 52.735 ;
        RECT 55.460 50.745 57.480 50.775 ;
        RECT 86.350 50.745 88.370 50.775 ;
        RECT 92.595 50.745 94.615 50.775 ;
        RECT 97.340 44.760 122.780 45.240 ;
        RECT 97.340 44.720 115.490 44.760 ;
        RECT 97.840 44.710 99.420 44.720 ;
        RECT 29.750 33.855 30.830 33.890 ;
        RECT 31.675 33.855 32.135 33.860 ;
        RECT 34.770 33.855 43.250 33.860 ;
        RECT 55.460 33.855 55.995 33.885 ;
        RECT 29.750 33.380 55.995 33.855 ;
        RECT 29.750 33.350 30.830 33.380 ;
        RECT 55.460 33.350 55.995 33.380 ;
        RECT 29.750 32.810 30.290 33.350 ;
        RECT 29.750 30.280 30.830 30.310 ;
        RECT 29.750 30.275 52.260 30.280 ;
        RECT 56.100 30.275 56.560 30.280 ;
        RECT 29.750 29.805 57.185 30.275 ;
        RECT 29.750 29.800 52.260 29.805 ;
        RECT 56.100 29.800 56.560 29.805 ;
        RECT 29.750 29.770 30.830 29.800 ;
        RECT 29.750 29.230 30.290 29.770 ;
        RECT 29.750 26.700 30.830 26.730 ;
        RECT 29.750 26.220 43.250 26.700 ;
        RECT 29.750 26.190 30.830 26.220 ;
        RECT 29.750 25.650 30.290 26.190 ;
        RECT 29.750 23.120 30.830 23.150 ;
        RECT 29.750 22.640 92.520 23.120 ;
        RECT 29.750 22.610 30.830 22.640 ;
        RECT 29.750 22.070 30.290 22.610 ;
        RECT 29.750 18.550 30.290 19.090 ;
        RECT 29.750 18.520 30.830 18.550 ;
        RECT 83.050 18.520 83.510 18.525 ;
        RECT 29.750 18.040 83.510 18.520 ;
        RECT 29.750 18.010 30.830 18.040 ;
        RECT 12.020 3.910 75.790 5.870 ;
        RECT 73.830 2.095 75.790 3.910 ;
        RECT 73.775 0.025 75.845 2.095 ;
      LAYER met2 ;
        RECT 105.190 165.370 107.230 166.395 ;
        RECT 105.220 164.345 107.200 165.370 ;
        RECT 105.190 163.320 107.230 164.345 ;
        RECT 105.220 162.295 107.200 163.320 ;
        RECT 105.190 161.270 107.230 162.295 ;
        RECT 105.220 159.835 107.200 161.270 ;
        RECT 105.190 158.810 107.230 159.835 ;
        RECT 105.220 157.785 107.200 158.810 ;
        RECT 105.190 156.760 107.230 157.785 ;
        RECT 105.220 155.325 107.200 156.760 ;
        RECT 105.190 154.300 107.230 155.325 ;
        RECT 68.480 152.970 69.020 153.510 ;
        RECT 105.220 153.275 107.200 154.300 ;
        RECT 68.510 149.870 68.990 152.970 ;
        RECT 105.190 152.250 107.230 153.275 ;
        RECT 105.220 151.225 107.200 152.250 ;
        RECT 105.190 150.200 107.230 151.225 ;
        RECT 68.480 149.330 69.020 149.870 ;
        RECT 68.510 146.230 68.990 149.330 ;
        RECT 105.220 149.175 107.200 150.200 ;
        RECT 105.190 148.150 107.230 149.175 ;
        RECT 105.220 146.715 107.200 148.150 ;
        RECT 68.480 145.690 69.020 146.230 ;
        RECT 105.190 145.690 107.230 146.715 ;
        RECT 105.220 144.665 107.200 145.690 ;
        RECT 105.190 143.640 107.230 144.665 ;
        RECT 105.220 142.615 107.200 143.640 ;
        RECT 105.190 141.590 107.230 142.615 ;
        RECT 68.480 139.245 69.020 139.785 ;
        RECT 105.220 139.775 107.200 141.590 ;
        RECT 68.510 136.145 68.990 139.245 ;
        RECT 105.190 138.750 107.230 139.775 ;
        RECT 105.220 137.725 107.200 138.750 ;
        RECT 105.190 136.700 107.230 137.725 ;
        RECT 68.480 135.605 69.020 136.145 ;
        RECT 105.220 135.675 107.200 136.700 ;
        RECT 68.510 132.505 68.990 135.605 ;
        RECT 105.190 134.650 107.230 135.675 ;
        RECT 105.220 133.215 107.200 134.650 ;
        RECT 68.480 131.965 69.020 132.505 ;
        RECT 105.190 132.190 107.230 133.215 ;
        RECT 105.220 131.165 107.200 132.190 ;
        RECT 105.190 130.140 107.230 131.165 ;
        RECT 105.220 129.115 107.200 130.140 ;
        RECT 105.190 128.090 107.230 129.115 ;
        RECT 105.220 126.655 107.200 128.090 ;
        RECT 105.190 125.630 107.230 126.655 ;
        RECT 105.220 124.605 107.200 125.630 ;
        RECT 105.190 123.580 107.230 124.605 ;
        RECT 105.220 122.555 107.200 123.580 ;
        RECT 105.195 121.530 107.235 122.555 ;
        RECT 105.220 120.095 107.200 121.530 ;
        RECT 105.190 119.070 107.230 120.095 ;
        RECT 105.220 87.780 107.180 119.070 ;
        RECT 92.595 85.760 94.615 87.780 ;
        RECT 105.190 85.760 107.210 87.780 ;
        RECT 92.625 52.765 94.585 85.760 ;
        RECT 12.050 3.880 14.010 52.765 ;
        RECT 55.460 50.745 57.480 52.765 ;
        RECT 86.350 50.745 88.370 52.765 ;
        RECT 92.595 50.745 94.615 52.765 ;
        RECT 29.750 33.350 30.830 33.890 ;
        RECT 55.490 33.885 55.965 50.745 ;
        RECT 86.530 45.250 87.090 50.745 ;
        RECT 86.530 44.690 87.570 45.250 ;
        RECT 95.955 44.710 98.920 45.240 ;
        RECT 55.460 33.350 55.995 33.885 ;
        RECT 29.750 32.810 30.290 33.350 ;
        RECT 29.780 30.310 30.260 32.810 ;
        RECT 29.750 29.770 30.830 30.310 ;
        RECT 29.750 29.230 30.290 29.770 ;
        RECT 29.780 26.730 30.260 29.230 ;
        RECT 29.750 26.190 30.830 26.730 ;
        RECT 29.750 25.650 30.290 26.190 ;
        RECT 29.780 23.150 30.260 25.650 ;
        RECT 29.750 22.610 30.830 23.150 ;
        RECT 29.750 22.070 30.290 22.610 ;
        RECT 29.780 19.090 30.260 22.070 ;
        RECT 29.750 18.550 30.290 19.090 ;
        RECT 29.750 18.010 30.830 18.550 ;
        RECT 73.775 0.025 75.845 2.095 ;
      LAYER met3 ;
        RECT 86.545 45.240 87.075 45.695 ;
        RECT 86.545 44.710 97.330 45.240 ;
        RECT 73.775 0.025 75.845 2.095 ;
      LAYER met4 ;
        RECT 73.775 0.025 75.845 2.095 ;
        RECT 74.530 0.000 75.430 0.025 ;
    END
  END ua[4]
  PIN ua[5]
    DIRECTION INOUT ;
    USE SIGNAL ;
    ANTENNADIFFAREA 59.041248 ;
    PORT
      LAYER pwell ;
        RECT 108.010 163.110 108.440 163.895 ;
        RECT 107.920 156.550 108.350 157.335 ;
        RECT 85.865 150.710 86.295 151.495 ;
        RECT 107.920 149.990 108.350 150.775 ;
        RECT 76.855 147.070 77.285 147.855 ;
        RECT 29.055 143.430 29.485 144.215 ;
        RECT 66.690 143.420 67.120 144.205 ;
        RECT 87.910 143.430 88.340 144.215 ;
        RECT 108.025 143.425 108.455 144.210 ;
        RECT 27.180 136.985 27.610 137.770 ;
        RECT 63.380 136.985 63.810 137.770 ;
        RECT 87.910 136.985 88.340 137.770 ;
        RECT 122.625 136.490 123.055 137.275 ;
        RECT 76.855 133.345 77.285 134.130 ;
        RECT 85.865 129.700 86.295 130.485 ;
        RECT 107.900 129.930 108.330 130.715 ;
        RECT 108.295 123.370 108.725 124.155 ;
        RECT 107.825 116.810 108.255 117.595 ;
        RECT 31.690 31.090 32.120 31.875 ;
        RECT 56.115 27.510 56.545 28.295 ;
        RECT 32.080 23.930 32.510 24.715 ;
        RECT 53.925 20.350 54.355 21.135 ;
        RECT 83.065 20.350 83.495 21.135 ;
        RECT 53.925 15.750 54.355 16.535 ;
        RECT 83.065 15.755 83.495 16.540 ;
      LAYER li1 ;
        RECT 108.080 163.005 108.370 163.730 ;
        RECT 110.775 163.005 111.105 163.405 ;
        RECT 111.715 163.005 112.045 163.405 ;
        RECT 112.555 163.005 112.885 163.405 ;
        RECT 113.395 163.005 113.725 163.405 ;
        RECT 114.235 163.005 114.575 163.405 ;
        RECT 107.995 162.835 108.455 163.005 ;
        RECT 110.260 162.835 118.540 163.005 ;
        RECT 107.990 156.445 108.280 157.170 ;
        RECT 110.775 156.445 111.105 156.845 ;
        RECT 111.715 156.445 112.045 156.845 ;
        RECT 112.555 156.445 112.885 156.845 ;
        RECT 113.395 156.445 113.725 156.845 ;
        RECT 114.235 156.445 114.575 156.845 ;
        RECT 107.905 156.275 108.365 156.445 ;
        RECT 110.260 156.275 118.540 156.445 ;
        RECT 85.935 150.605 86.225 151.330 ;
        RECT 89.950 150.605 90.180 151.405 ;
        RECT 90.850 150.605 91.020 151.065 ;
        RECT 91.690 150.605 91.860 151.065 ;
        RECT 92.530 150.605 92.700 151.065 ;
        RECT 93.370 150.605 93.540 151.065 ;
        RECT 94.210 150.605 94.380 151.065 ;
        RECT 95.050 150.605 95.220 151.065 ;
        RECT 95.890 150.605 96.060 151.065 ;
        RECT 96.730 150.605 96.940 151.405 ;
        RECT 85.850 150.435 86.310 150.605 ;
        RECT 89.770 150.435 97.130 150.605 ;
        RECT 107.990 149.885 108.280 150.610 ;
        RECT 110.775 149.885 111.105 150.285 ;
        RECT 111.715 149.885 112.045 150.285 ;
        RECT 112.555 149.885 112.885 150.285 ;
        RECT 113.395 149.885 113.725 150.285 ;
        RECT 114.235 149.885 114.575 150.285 ;
        RECT 107.905 149.715 108.365 149.885 ;
        RECT 110.260 149.715 118.540 149.885 ;
        RECT 76.925 146.965 77.215 147.690 ;
        RECT 79.130 146.965 79.360 147.765 ;
        RECT 80.030 146.965 80.200 147.425 ;
        RECT 80.870 146.965 81.040 147.425 ;
        RECT 81.710 146.965 81.880 147.425 ;
        RECT 82.550 146.965 82.720 147.425 ;
        RECT 83.390 146.965 83.560 147.425 ;
        RECT 84.230 146.965 84.400 147.425 ;
        RECT 85.070 146.965 85.240 147.425 ;
        RECT 85.910 146.965 86.120 147.765 ;
        RECT 89.950 146.965 90.180 147.765 ;
        RECT 90.850 146.965 91.020 147.425 ;
        RECT 91.690 146.965 91.860 147.425 ;
        RECT 92.530 146.965 92.700 147.425 ;
        RECT 93.370 146.965 93.540 147.425 ;
        RECT 94.210 146.965 94.380 147.425 ;
        RECT 95.050 146.965 95.220 147.425 ;
        RECT 95.890 146.965 96.060 147.425 ;
        RECT 96.730 146.965 96.940 147.765 ;
        RECT 76.840 146.795 77.300 146.965 ;
        RECT 78.950 146.795 86.310 146.965 ;
        RECT 89.770 146.795 97.130 146.965 ;
        RECT 29.125 143.325 29.415 144.050 ;
        RECT 32.635 143.325 32.945 144.125 ;
        RECT 35.905 143.325 36.135 144.145 ;
        RECT 38.935 143.325 39.165 144.145 ;
        RECT 41.770 143.325 42.000 144.145 ;
        RECT 42.670 143.325 42.880 144.145 ;
        RECT 44.805 143.325 45.070 143.785 ;
        RECT 45.740 143.325 45.910 143.785 ;
        RECT 46.580 143.325 46.830 143.790 ;
        RECT 48.885 143.325 49.140 143.785 ;
        RECT 49.810 143.325 49.980 143.785 ;
        RECT 50.650 143.325 50.820 143.785 ;
        RECT 51.490 143.325 51.660 143.785 ;
        RECT 52.330 143.325 52.635 143.785 ;
        RECT 54.675 143.325 54.930 143.785 ;
        RECT 55.600 143.325 55.770 143.785 ;
        RECT 56.440 143.325 56.610 143.785 ;
        RECT 57.280 143.325 57.450 143.785 ;
        RECT 58.120 143.325 58.290 143.785 ;
        RECT 58.960 143.325 59.130 143.785 ;
        RECT 59.975 143.325 60.315 143.785 ;
        RECT 29.040 143.155 29.500 143.325 ;
        RECT 32.550 143.155 33.930 143.325 ;
        RECT 35.585 143.155 36.965 143.325 ;
        RECT 38.615 143.155 39.995 143.325 ;
        RECT 41.645 143.155 43.025 143.325 ;
        RECT 44.675 143.155 46.975 143.325 ;
        RECT 48.630 143.155 52.770 143.325 ;
        RECT 54.420 143.155 60.400 143.325 ;
        RECT 66.760 143.315 67.050 144.040 ;
        RECT 70.120 143.325 70.350 144.125 ;
        RECT 71.020 143.325 71.190 143.785 ;
        RECT 71.860 143.325 72.030 143.785 ;
        RECT 72.700 143.325 72.870 143.785 ;
        RECT 73.540 143.325 73.710 143.785 ;
        RECT 74.380 143.325 74.550 143.785 ;
        RECT 75.220 143.325 75.390 143.785 ;
        RECT 76.060 143.325 76.230 143.785 ;
        RECT 76.900 143.325 77.110 144.125 ;
        RECT 79.130 143.325 79.360 144.125 ;
        RECT 80.030 143.325 80.200 143.785 ;
        RECT 80.870 143.325 81.040 143.785 ;
        RECT 81.710 143.325 81.880 143.785 ;
        RECT 82.550 143.325 82.720 143.785 ;
        RECT 83.390 143.325 83.560 143.785 ;
        RECT 84.230 143.325 84.400 143.785 ;
        RECT 85.070 143.325 85.240 143.785 ;
        RECT 85.910 143.325 86.120 144.125 ;
        RECT 87.980 143.325 88.270 144.050 ;
        RECT 89.950 143.325 90.180 144.125 ;
        RECT 90.850 143.325 91.020 143.785 ;
        RECT 91.690 143.325 91.860 143.785 ;
        RECT 92.530 143.325 92.700 143.785 ;
        RECT 93.370 143.325 93.540 143.785 ;
        RECT 94.210 143.325 94.380 143.785 ;
        RECT 95.050 143.325 95.220 143.785 ;
        RECT 95.890 143.325 96.060 143.785 ;
        RECT 96.730 143.325 96.940 144.125 ;
        RECT 66.675 143.145 67.135 143.315 ;
        RECT 69.940 143.155 77.300 143.325 ;
        RECT 78.950 143.155 86.310 143.325 ;
        RECT 87.895 143.155 88.355 143.325 ;
        RECT 89.770 143.155 97.130 143.325 ;
        RECT 108.095 143.320 108.385 144.045 ;
        RECT 110.775 143.325 111.105 143.725 ;
        RECT 111.715 143.325 112.045 143.725 ;
        RECT 112.555 143.325 112.885 143.725 ;
        RECT 113.395 143.325 113.725 143.725 ;
        RECT 114.235 143.325 114.575 143.725 ;
        RECT 108.010 143.150 108.470 143.320 ;
        RECT 110.260 143.155 118.540 143.325 ;
        RECT 27.250 136.880 27.540 137.605 ;
        RECT 29.645 136.880 29.875 137.700 ;
        RECT 30.545 136.880 30.755 137.700 ;
        RECT 32.635 136.880 32.945 137.680 ;
        RECT 35.900 136.880 36.130 137.700 ;
        RECT 38.930 136.880 39.160 137.700 ;
        RECT 41.765 136.880 41.995 137.700 ;
        RECT 42.665 136.880 42.875 137.700 ;
        RECT 44.800 136.880 45.065 137.340 ;
        RECT 45.735 136.880 45.905 137.340 ;
        RECT 46.575 136.880 46.825 137.345 ;
        RECT 48.875 136.880 49.130 137.340 ;
        RECT 49.800 136.880 49.970 137.340 ;
        RECT 50.640 136.880 50.810 137.340 ;
        RECT 51.480 136.880 51.650 137.340 ;
        RECT 52.320 136.880 52.625 137.340 ;
        RECT 54.665 136.880 54.920 137.340 ;
        RECT 55.590 136.880 55.760 137.340 ;
        RECT 56.430 136.880 56.600 137.340 ;
        RECT 57.270 136.880 57.440 137.340 ;
        RECT 58.110 136.880 58.280 137.340 ;
        RECT 58.950 136.880 59.120 137.340 ;
        RECT 59.965 136.880 60.305 137.340 ;
        RECT 63.450 136.880 63.740 137.605 ;
        RECT 70.120 136.880 70.350 137.680 ;
        RECT 71.020 136.880 71.190 137.340 ;
        RECT 71.860 136.880 72.030 137.340 ;
        RECT 72.700 136.880 72.870 137.340 ;
        RECT 73.540 136.880 73.710 137.340 ;
        RECT 74.380 136.880 74.550 137.340 ;
        RECT 75.220 136.880 75.390 137.340 ;
        RECT 76.060 136.880 76.230 137.340 ;
        RECT 76.900 136.880 77.110 137.680 ;
        RECT 79.130 136.880 79.360 137.680 ;
        RECT 80.030 136.880 80.200 137.340 ;
        RECT 80.870 136.880 81.040 137.340 ;
        RECT 81.710 136.880 81.880 137.340 ;
        RECT 82.550 136.880 82.720 137.340 ;
        RECT 83.390 136.880 83.560 137.340 ;
        RECT 84.230 136.880 84.400 137.340 ;
        RECT 85.070 136.880 85.240 137.340 ;
        RECT 85.910 136.880 86.120 137.680 ;
        RECT 87.980 136.880 88.270 137.605 ;
        RECT 89.950 136.880 90.180 137.680 ;
        RECT 90.850 136.880 91.020 137.340 ;
        RECT 91.690 136.880 91.860 137.340 ;
        RECT 92.530 136.880 92.700 137.340 ;
        RECT 93.370 136.880 93.540 137.340 ;
        RECT 94.210 136.880 94.380 137.340 ;
        RECT 95.050 136.880 95.220 137.340 ;
        RECT 95.890 136.880 96.060 137.340 ;
        RECT 96.730 136.880 96.940 137.680 ;
        RECT 27.165 136.710 27.625 136.880 ;
        RECT 29.520 136.710 30.900 136.880 ;
        RECT 32.550 136.710 33.930 136.880 ;
        RECT 35.580 136.710 36.960 136.880 ;
        RECT 38.610 136.710 39.990 136.880 ;
        RECT 41.640 136.710 43.020 136.880 ;
        RECT 44.670 136.710 46.970 136.880 ;
        RECT 48.620 136.710 52.760 136.880 ;
        RECT 54.410 136.710 60.390 136.880 ;
        RECT 63.365 136.710 63.825 136.880 ;
        RECT 69.940 136.710 77.300 136.880 ;
        RECT 78.950 136.710 86.310 136.880 ;
        RECT 87.895 136.710 88.355 136.880 ;
        RECT 89.770 136.710 97.130 136.880 ;
        RECT 110.775 136.385 111.105 136.785 ;
        RECT 111.715 136.385 112.045 136.785 ;
        RECT 112.555 136.385 112.885 136.785 ;
        RECT 113.395 136.385 113.725 136.785 ;
        RECT 114.235 136.385 114.575 136.785 ;
        RECT 122.695 136.385 122.985 137.110 ;
        RECT 110.260 136.215 118.540 136.385 ;
        RECT 122.610 136.215 123.070 136.385 ;
        RECT 76.925 133.240 77.215 133.965 ;
        RECT 79.130 133.240 79.360 134.040 ;
        RECT 80.030 133.240 80.200 133.700 ;
        RECT 80.870 133.240 81.040 133.700 ;
        RECT 81.710 133.240 81.880 133.700 ;
        RECT 82.550 133.240 82.720 133.700 ;
        RECT 83.390 133.240 83.560 133.700 ;
        RECT 84.230 133.240 84.400 133.700 ;
        RECT 85.070 133.240 85.240 133.700 ;
        RECT 85.910 133.240 86.120 134.040 ;
        RECT 89.950 133.240 90.180 134.040 ;
        RECT 90.850 133.240 91.020 133.700 ;
        RECT 91.690 133.240 91.860 133.700 ;
        RECT 92.530 133.240 92.700 133.700 ;
        RECT 93.370 133.240 93.540 133.700 ;
        RECT 94.210 133.240 94.380 133.700 ;
        RECT 95.050 133.240 95.220 133.700 ;
        RECT 95.890 133.240 96.060 133.700 ;
        RECT 96.730 133.240 96.940 134.040 ;
        RECT 76.840 133.070 77.300 133.240 ;
        RECT 78.950 133.070 86.310 133.240 ;
        RECT 89.770 133.070 97.130 133.240 ;
        RECT 85.935 129.595 86.225 130.320 ;
        RECT 85.850 129.425 86.310 129.595 ;
        RECT 89.950 129.590 90.180 130.390 ;
        RECT 90.850 129.590 91.020 130.050 ;
        RECT 91.690 129.590 91.860 130.050 ;
        RECT 92.530 129.590 92.700 130.050 ;
        RECT 93.370 129.590 93.540 130.050 ;
        RECT 94.210 129.590 94.380 130.050 ;
        RECT 95.050 129.590 95.220 130.050 ;
        RECT 95.890 129.590 96.060 130.050 ;
        RECT 96.730 129.590 96.940 130.390 ;
        RECT 107.970 129.825 108.260 130.550 ;
        RECT 110.775 129.825 111.105 130.225 ;
        RECT 111.715 129.825 112.045 130.225 ;
        RECT 112.555 129.825 112.885 130.225 ;
        RECT 113.395 129.825 113.725 130.225 ;
        RECT 114.235 129.825 114.575 130.225 ;
        RECT 107.885 129.655 108.345 129.825 ;
        RECT 110.260 129.655 118.540 129.825 ;
        RECT 89.770 129.420 97.130 129.590 ;
        RECT 108.365 123.265 108.655 123.990 ;
        RECT 110.775 123.265 111.105 123.665 ;
        RECT 111.715 123.265 112.045 123.665 ;
        RECT 112.555 123.265 112.885 123.665 ;
        RECT 113.395 123.265 113.725 123.665 ;
        RECT 114.235 123.265 114.575 123.665 ;
        RECT 108.280 123.095 108.740 123.265 ;
        RECT 110.260 123.095 118.540 123.265 ;
        RECT 107.895 116.705 108.185 117.430 ;
        RECT 110.775 116.705 111.105 117.105 ;
        RECT 111.715 116.705 112.045 117.105 ;
        RECT 112.555 116.705 112.885 117.105 ;
        RECT 113.395 116.705 113.725 117.105 ;
        RECT 114.235 116.705 114.575 117.105 ;
        RECT 107.810 116.535 108.270 116.705 ;
        RECT 110.260 116.535 118.540 116.705 ;
        RECT 31.760 30.985 32.050 31.710 ;
        RECT 36.070 30.985 36.300 31.785 ;
        RECT 36.970 30.985 37.140 31.445 ;
        RECT 37.810 30.985 37.980 31.445 ;
        RECT 38.650 30.985 38.820 31.445 ;
        RECT 39.490 30.985 39.660 31.445 ;
        RECT 40.330 30.985 40.500 31.445 ;
        RECT 41.170 30.985 41.340 31.445 ;
        RECT 42.010 30.985 42.180 31.445 ;
        RECT 42.850 30.985 43.060 31.785 ;
        RECT 31.675 30.815 32.135 30.985 ;
        RECT 35.890 30.815 43.250 30.985 ;
        RECT 36.070 27.405 36.300 28.205 ;
        RECT 36.970 27.405 37.140 27.865 ;
        RECT 37.810 27.405 37.980 27.865 ;
        RECT 38.650 27.405 38.820 27.865 ;
        RECT 39.490 27.405 39.660 27.865 ;
        RECT 40.330 27.405 40.500 27.865 ;
        RECT 41.170 27.405 41.340 27.865 ;
        RECT 42.010 27.405 42.180 27.865 ;
        RECT 42.850 27.405 43.060 28.205 ;
        RECT 45.080 27.405 45.310 28.205 ;
        RECT 45.980 27.405 46.150 27.865 ;
        RECT 46.820 27.405 46.990 27.865 ;
        RECT 47.660 27.405 47.830 27.865 ;
        RECT 48.500 27.405 48.670 27.865 ;
        RECT 49.340 27.405 49.510 27.865 ;
        RECT 50.180 27.405 50.350 27.865 ;
        RECT 51.020 27.405 51.190 27.865 ;
        RECT 51.860 27.405 52.070 28.205 ;
        RECT 56.185 27.405 56.475 28.130 ;
        RECT 35.890 27.235 43.250 27.405 ;
        RECT 44.900 27.235 52.260 27.405 ;
        RECT 56.100 27.235 56.560 27.405 ;
        RECT 32.150 23.825 32.440 24.550 ;
        RECT 36.070 23.825 36.300 24.625 ;
        RECT 36.970 23.825 37.140 24.285 ;
        RECT 37.810 23.825 37.980 24.285 ;
        RECT 38.650 23.825 38.820 24.285 ;
        RECT 39.490 23.825 39.660 24.285 ;
        RECT 40.330 23.825 40.500 24.285 ;
        RECT 41.170 23.825 41.340 24.285 ;
        RECT 42.010 23.825 42.180 24.285 ;
        RECT 42.850 23.825 43.060 24.625 ;
        RECT 32.065 23.655 32.525 23.825 ;
        RECT 35.890 23.655 43.250 23.825 ;
        RECT 36.070 20.245 36.300 21.045 ;
        RECT 36.970 20.245 37.140 20.705 ;
        RECT 37.810 20.245 37.980 20.705 ;
        RECT 38.650 20.245 38.820 20.705 ;
        RECT 39.490 20.245 39.660 20.705 ;
        RECT 40.330 20.245 40.500 20.705 ;
        RECT 41.170 20.245 41.340 20.705 ;
        RECT 42.010 20.245 42.180 20.705 ;
        RECT 42.850 20.245 43.060 21.045 ;
        RECT 45.080 20.245 45.310 21.045 ;
        RECT 45.980 20.245 46.150 20.705 ;
        RECT 46.820 20.245 46.990 20.705 ;
        RECT 47.660 20.245 47.830 20.705 ;
        RECT 48.500 20.245 48.670 20.705 ;
        RECT 49.340 20.245 49.510 20.705 ;
        RECT 50.180 20.245 50.350 20.705 ;
        RECT 51.020 20.245 51.190 20.705 ;
        RECT 51.860 20.245 52.070 21.045 ;
        RECT 53.995 20.245 54.285 20.970 ;
        RECT 56.200 20.245 56.430 21.045 ;
        RECT 57.100 20.245 57.270 20.705 ;
        RECT 57.940 20.245 58.110 20.705 ;
        RECT 58.780 20.245 58.950 20.705 ;
        RECT 59.620 20.245 59.790 20.705 ;
        RECT 60.460 20.245 60.630 20.705 ;
        RECT 61.300 20.245 61.470 20.705 ;
        RECT 62.140 20.245 62.310 20.705 ;
        RECT 62.980 20.245 63.190 21.045 ;
        RECT 65.210 20.245 65.440 21.045 ;
        RECT 66.110 20.245 66.280 20.705 ;
        RECT 66.950 20.245 67.120 20.705 ;
        RECT 67.790 20.245 67.960 20.705 ;
        RECT 68.630 20.245 68.800 20.705 ;
        RECT 69.470 20.245 69.640 20.705 ;
        RECT 70.310 20.245 70.480 20.705 ;
        RECT 71.150 20.245 71.320 20.705 ;
        RECT 71.990 20.245 72.200 21.045 ;
        RECT 74.220 20.245 74.450 21.045 ;
        RECT 75.120 20.245 75.290 20.705 ;
        RECT 75.960 20.245 76.130 20.705 ;
        RECT 76.800 20.245 76.970 20.705 ;
        RECT 77.640 20.245 77.810 20.705 ;
        RECT 78.480 20.245 78.650 20.705 ;
        RECT 79.320 20.245 79.490 20.705 ;
        RECT 80.160 20.245 80.330 20.705 ;
        RECT 81.000 20.245 81.210 21.045 ;
        RECT 83.135 20.245 83.425 20.970 ;
        RECT 85.340 20.245 85.570 21.045 ;
        RECT 86.240 20.245 86.410 20.705 ;
        RECT 87.080 20.245 87.250 20.705 ;
        RECT 87.920 20.245 88.090 20.705 ;
        RECT 88.760 20.245 88.930 20.705 ;
        RECT 89.600 20.245 89.770 20.705 ;
        RECT 90.440 20.245 90.610 20.705 ;
        RECT 91.280 20.245 91.450 20.705 ;
        RECT 92.120 20.245 92.330 21.045 ;
        RECT 35.890 20.075 43.250 20.245 ;
        RECT 44.900 20.075 52.260 20.245 ;
        RECT 53.910 20.075 54.370 20.245 ;
        RECT 56.020 20.075 63.380 20.245 ;
        RECT 65.030 20.075 72.390 20.245 ;
        RECT 74.040 20.075 81.400 20.245 ;
        RECT 83.050 20.075 83.510 20.245 ;
        RECT 85.160 20.075 92.520 20.245 ;
        RECT 36.070 15.645 36.300 16.445 ;
        RECT 36.970 15.645 37.140 16.105 ;
        RECT 37.810 15.645 37.980 16.105 ;
        RECT 38.650 15.645 38.820 16.105 ;
        RECT 39.490 15.645 39.660 16.105 ;
        RECT 40.330 15.645 40.500 16.105 ;
        RECT 41.170 15.645 41.340 16.105 ;
        RECT 42.010 15.645 42.180 16.105 ;
        RECT 42.850 15.645 43.060 16.445 ;
        RECT 45.080 15.645 45.310 16.445 ;
        RECT 45.980 15.645 46.150 16.105 ;
        RECT 46.820 15.645 46.990 16.105 ;
        RECT 47.660 15.645 47.830 16.105 ;
        RECT 48.500 15.645 48.670 16.105 ;
        RECT 49.340 15.645 49.510 16.105 ;
        RECT 50.180 15.645 50.350 16.105 ;
        RECT 51.020 15.645 51.190 16.105 ;
        RECT 51.860 15.645 52.070 16.445 ;
        RECT 53.995 15.645 54.285 16.370 ;
        RECT 56.200 15.645 56.430 16.445 ;
        RECT 57.100 15.645 57.270 16.105 ;
        RECT 57.940 15.645 58.110 16.105 ;
        RECT 58.780 15.645 58.950 16.105 ;
        RECT 59.620 15.645 59.790 16.105 ;
        RECT 60.460 15.645 60.630 16.105 ;
        RECT 61.300 15.645 61.470 16.105 ;
        RECT 62.140 15.645 62.310 16.105 ;
        RECT 62.980 15.645 63.190 16.445 ;
        RECT 65.210 15.645 65.440 16.445 ;
        RECT 66.110 15.645 66.280 16.105 ;
        RECT 66.950 15.645 67.120 16.105 ;
        RECT 67.790 15.645 67.960 16.105 ;
        RECT 68.630 15.645 68.800 16.105 ;
        RECT 69.470 15.645 69.640 16.105 ;
        RECT 70.310 15.645 70.480 16.105 ;
        RECT 71.150 15.645 71.320 16.105 ;
        RECT 71.990 15.645 72.200 16.445 ;
        RECT 74.220 15.645 74.450 16.445 ;
        RECT 75.120 15.645 75.290 16.105 ;
        RECT 75.960 15.645 76.130 16.105 ;
        RECT 76.800 15.645 76.970 16.105 ;
        RECT 77.640 15.645 77.810 16.105 ;
        RECT 78.480 15.645 78.650 16.105 ;
        RECT 79.320 15.645 79.490 16.105 ;
        RECT 80.160 15.645 80.330 16.105 ;
        RECT 81.000 15.645 81.210 16.445 ;
        RECT 83.135 15.650 83.425 16.375 ;
        RECT 35.890 15.475 43.250 15.645 ;
        RECT 44.900 15.475 52.260 15.645 ;
        RECT 53.910 15.475 54.370 15.645 ;
        RECT 56.020 15.475 63.380 15.645 ;
        RECT 65.030 15.475 72.390 15.645 ;
        RECT 74.040 15.475 81.400 15.645 ;
        RECT 83.050 15.480 83.510 15.650 ;
      LAYER met1 ;
        RECT 123.945 179.180 128.035 179.210 ;
        RECT 137.235 179.180 139.275 179.210 ;
        RECT 123.945 177.200 139.275 179.180 ;
        RECT 123.945 177.170 128.035 177.200 ;
        RECT 137.235 177.170 139.275 177.200 ;
        RECT 123.945 175.130 125.990 177.170 ;
        RECT 123.945 163.160 125.985 163.225 ;
        RECT 107.995 162.200 125.985 163.160 ;
        RECT 123.975 161.175 125.955 162.200 ;
        RECT 123.945 160.150 125.985 161.175 ;
        RECT 123.975 159.125 125.955 160.150 ;
        RECT 123.945 158.100 125.985 159.125 ;
        RECT 123.975 156.665 125.955 158.100 ;
        RECT 123.945 156.600 125.985 156.665 ;
        RECT 107.905 155.640 125.985 156.600 ;
        RECT 123.975 154.615 125.955 155.640 ;
        RECT 123.945 153.590 125.985 154.615 ;
        RECT 123.975 152.155 125.955 153.590 ;
        RECT 123.945 151.130 125.985 152.155 ;
        RECT 65.125 150.760 65.665 150.790 ;
        RECT 99.325 150.760 99.865 150.790 ;
        RECT 65.125 150.280 99.865 150.760 ;
        RECT 65.125 150.250 65.665 150.280 ;
        RECT 99.325 150.250 99.865 150.280 ;
        RECT 123.975 150.105 125.955 151.130 ;
        RECT 123.945 150.040 125.985 150.105 ;
        RECT 107.905 149.080 125.985 150.040 ;
        RECT 123.975 148.055 125.955 149.080 ;
        RECT 65.125 147.120 65.665 147.150 ;
        RECT 99.325 147.120 99.865 147.150 ;
        RECT 65.125 146.640 99.865 147.120 ;
        RECT 123.945 147.030 125.985 148.055 ;
        RECT 65.125 146.610 65.665 146.640 ;
        RECT 99.325 146.610 99.865 146.640 ;
        RECT 123.975 146.005 125.955 147.030 ;
        RECT 123.945 144.980 125.985 146.005 ;
        RECT 123.975 143.545 125.955 144.980 ;
        RECT 65.125 143.480 65.665 143.510 ;
        RECT 99.325 143.480 99.865 143.510 ;
        RECT 123.945 143.480 125.985 143.545 ;
        RECT 29.040 143.000 99.865 143.480 ;
        RECT 65.125 142.970 65.665 143.000 ;
        RECT 66.675 142.990 67.135 143.000 ;
        RECT 99.325 142.970 99.865 143.000 ;
        RECT 108.010 142.520 125.985 143.480 ;
        RECT 123.975 141.495 125.955 142.520 ;
        RECT 123.945 140.470 125.985 141.495 ;
        RECT 123.975 139.445 125.955 140.470 ;
        RECT 123.945 138.420 125.985 139.445 ;
        RECT 65.125 137.035 65.665 137.065 ;
        RECT 99.325 137.035 99.865 137.060 ;
        RECT 27.165 136.555 99.865 137.035 ;
        RECT 123.975 136.605 125.955 138.420 ;
        RECT 65.125 136.525 65.665 136.555 ;
        RECT 99.325 136.520 99.865 136.555 ;
        RECT 123.945 136.540 125.985 136.605 ;
        RECT 110.260 136.060 125.985 136.540 ;
        RECT 110.265 135.580 125.985 136.060 ;
        RECT 123.975 134.555 125.955 135.580 ;
        RECT 123.945 133.530 125.985 134.555 ;
        RECT 65.125 133.395 65.665 133.425 ;
        RECT 99.325 133.395 99.865 133.425 ;
        RECT 65.125 132.915 99.865 133.395 ;
        RECT 65.125 132.885 65.665 132.915 ;
        RECT 99.325 132.885 99.865 132.915 ;
        RECT 123.975 132.505 125.955 133.530 ;
        RECT 123.945 131.480 125.985 132.505 ;
        RECT 123.975 130.045 125.955 131.480 ;
        RECT 123.945 129.980 125.985 130.045 ;
        RECT 65.125 129.745 65.665 129.775 ;
        RECT 85.850 129.745 86.310 129.750 ;
        RECT 99.325 129.745 99.865 129.775 ;
        RECT 65.125 129.265 99.865 129.745 ;
        RECT 65.125 129.235 65.665 129.265 ;
        RECT 99.325 129.235 99.865 129.265 ;
        RECT 107.885 129.020 125.985 129.980 ;
        RECT 123.975 127.995 125.955 129.020 ;
        RECT 123.945 126.970 125.985 127.995 ;
        RECT 123.975 125.945 125.955 126.970 ;
        RECT 123.945 124.920 125.985 125.945 ;
        RECT 123.975 123.485 125.955 124.920 ;
        RECT 123.945 123.420 125.985 123.485 ;
        RECT 108.280 122.460 125.985 123.420 ;
        RECT 123.975 121.435 125.955 122.460 ;
        RECT 123.945 120.410 125.985 121.435 ;
        RECT 123.975 119.385 125.955 120.410 ;
        RECT 123.950 118.360 125.985 119.385 ;
        RECT 123.975 116.925 125.955 118.360 ;
        RECT 99.295 116.860 100.315 116.890 ;
        RECT 123.945 116.860 125.985 116.925 ;
        RECT 99.295 115.900 125.985 116.860 ;
        RECT 99.295 115.870 100.315 115.900 ;
        RECT 25.785 31.140 26.865 31.170 ;
        RECT 25.785 30.660 43.250 31.140 ;
        RECT 25.785 30.630 26.865 30.660 ;
        RECT 25.785 30.090 26.325 30.630 ;
        RECT 25.785 27.560 26.325 28.130 ;
        RECT 25.785 27.080 57.115 27.560 ;
        RECT 25.785 26.510 26.325 27.080 ;
        RECT 25.785 23.980 26.325 24.550 ;
        RECT 25.785 23.500 43.250 23.980 ;
        RECT 25.785 22.930 26.325 23.500 ;
        RECT 25.785 20.400 26.325 20.970 ;
        RECT 25.785 19.920 92.520 20.400 ;
        RECT 25.785 19.350 26.325 19.920 ;
        RECT 25.785 15.830 26.325 16.370 ;
        RECT 25.785 15.800 26.865 15.830 ;
        RECT 83.050 15.800 83.510 15.805 ;
        RECT 92.745 15.800 93.285 15.830 ;
        RECT 25.785 15.320 93.285 15.800 ;
        RECT 25.785 15.290 26.865 15.320 ;
        RECT 92.745 15.290 93.285 15.320 ;
      LAYER met2 ;
        RECT 123.945 177.170 128.035 179.210 ;
        RECT 137.235 177.170 139.275 179.210 ;
        RECT 123.945 175.130 125.990 177.170 ;
        RECT 123.975 163.225 125.955 175.130 ;
        RECT 123.945 162.200 125.985 163.225 ;
        RECT 123.975 161.175 125.955 162.200 ;
        RECT 123.945 160.150 125.985 161.175 ;
        RECT 123.975 159.125 125.955 160.150 ;
        RECT 123.945 158.100 125.985 159.125 ;
        RECT 123.975 156.665 125.955 158.100 ;
        RECT 123.945 155.640 125.985 156.665 ;
        RECT 123.975 154.615 125.955 155.640 ;
        RECT 123.945 153.590 125.985 154.615 ;
        RECT 123.975 152.155 125.955 153.590 ;
        RECT 123.945 151.130 125.985 152.155 ;
        RECT 65.125 150.250 65.665 150.790 ;
        RECT 65.155 147.150 65.635 150.250 ;
        RECT 65.125 146.610 65.665 147.150 ;
        RECT 65.155 143.510 65.635 146.610 ;
        RECT 65.125 142.970 65.665 143.510 ;
        RECT 65.125 136.525 65.665 137.065 ;
        RECT 65.155 133.425 65.635 136.525 ;
        RECT 65.125 132.885 65.665 133.425 ;
        RECT 65.155 129.775 65.635 132.885 ;
        RECT 65.125 129.235 65.665 129.775 ;
        RECT 99.325 116.890 99.865 150.790 ;
        RECT 123.975 150.105 125.955 151.130 ;
        RECT 123.945 149.080 125.985 150.105 ;
        RECT 123.975 148.055 125.955 149.080 ;
        RECT 123.945 147.030 125.985 148.055 ;
        RECT 123.975 146.005 125.955 147.030 ;
        RECT 123.945 144.980 125.985 146.005 ;
        RECT 123.975 143.545 125.955 144.980 ;
        RECT 123.945 142.520 125.985 143.545 ;
        RECT 123.975 141.495 125.955 142.520 ;
        RECT 123.945 140.470 125.985 141.495 ;
        RECT 123.975 139.445 125.955 140.470 ;
        RECT 123.945 138.420 125.985 139.445 ;
        RECT 123.975 136.605 125.955 138.420 ;
        RECT 123.945 135.580 125.985 136.605 ;
        RECT 123.975 134.555 125.955 135.580 ;
        RECT 123.945 133.530 125.985 134.555 ;
        RECT 123.975 132.505 125.955 133.530 ;
        RECT 123.945 131.480 125.985 132.505 ;
        RECT 123.975 130.045 125.955 131.480 ;
        RECT 123.945 129.020 125.985 130.045 ;
        RECT 123.975 127.995 125.955 129.020 ;
        RECT 123.945 126.970 125.985 127.995 ;
        RECT 123.975 125.945 125.955 126.970 ;
        RECT 123.945 124.920 125.985 125.945 ;
        RECT 123.975 123.485 125.955 124.920 ;
        RECT 123.945 122.460 125.985 123.485 ;
        RECT 123.975 121.435 125.955 122.460 ;
        RECT 123.945 120.410 125.985 121.435 ;
        RECT 123.975 119.385 125.955 120.410 ;
        RECT 123.950 118.360 125.985 119.385 ;
        RECT 123.975 116.925 125.955 118.360 ;
        RECT 99.295 115.870 100.315 116.890 ;
        RECT 123.945 115.900 125.985 116.925 ;
        RECT 25.785 30.630 26.865 31.170 ;
        RECT 25.785 30.090 26.325 30.630 ;
        RECT 25.815 28.130 26.295 30.090 ;
        RECT 25.785 26.510 26.325 28.130 ;
        RECT 25.815 24.550 26.295 26.510 ;
        RECT 25.785 22.930 26.325 24.550 ;
        RECT 25.815 20.970 26.295 22.930 ;
        RECT 25.785 19.350 26.325 20.970 ;
        RECT 25.815 16.370 26.295 19.350 ;
        RECT 25.785 15.830 26.325 16.370 ;
        RECT 25.785 15.290 26.865 15.830 ;
        RECT 92.745 15.290 93.285 15.830 ;
        RECT 92.775 10.100 93.255 15.290 ;
        RECT 92.150 7.840 94.390 10.100 ;
        RECT 137.265 7.965 139.245 177.170 ;
      LAYER met3 ;
        RECT 54.670 7.985 139.270 9.965 ;
      LAYER met4 ;
        RECT 54.695 0.000 56.675 9.970 ;
    END
  END ua[5]
  PIN ua[6]
    DIRECTION INOUT ;
    USE SIGNAL ;
    PORT
      LAYER met4 ;
        RECT 4.410 225.760 138.750 225.765 ;
        RECT 3.990 224.560 138.750 225.760 ;
        RECT 4.000 223.430 138.750 224.560 ;
        RECT 4.000 1.820 6.000 223.430 ;
        RECT 4.000 0.000 40.410 1.820 ;
    END
  END ua[6]
  PIN VDPWR
    DIRECTION INOUT ;
    USE POWER ;
    PORT
      LAYER met4 ;
        RECT 1.000 5.000 3.000 220.760 ;
    END
  END VDPWR
  OBS
      LAYER pwell ;
        RECT 110.265 163.025 118.510 163.935 ;
        RECT 110.410 162.835 110.580 163.025 ;
        RECT 110.265 156.465 118.510 157.375 ;
        RECT 110.410 156.275 110.580 156.465 ;
        RECT 89.840 150.625 97.070 151.535 ;
        RECT 89.915 150.435 90.085 150.625 ;
        RECT 110.265 149.905 118.510 150.815 ;
        RECT 110.410 149.715 110.580 149.905 ;
        RECT 79.020 146.985 86.250 147.895 ;
        RECT 89.840 146.985 97.070 147.895 ;
        RECT 79.095 146.795 79.265 146.985 ;
        RECT 89.915 146.795 90.085 146.985 ;
        RECT 32.575 143.345 33.925 144.255 ;
        RECT 35.795 143.345 36.725 144.255 ;
        RECT 38.825 143.345 39.755 144.255 ;
        RECT 41.660 143.345 43.010 144.255 ;
        RECT 44.730 143.345 46.920 144.255 ;
        RECT 48.800 143.345 52.670 144.255 ;
        RECT 54.590 143.345 60.395 144.255 ;
        RECT 70.010 143.345 77.240 144.255 ;
        RECT 79.020 143.345 86.250 144.255 ;
        RECT 89.840 143.345 97.070 144.255 ;
        RECT 110.265 143.345 118.510 144.255 ;
        RECT 32.690 143.155 32.860 143.345 ;
        RECT 35.795 143.325 35.900 143.345 ;
        RECT 38.825 143.325 38.930 143.345 ;
        RECT 35.730 143.155 35.900 143.325 ;
        RECT 38.760 143.155 38.930 143.325 ;
        RECT 41.790 143.155 41.960 143.345 ;
        RECT 44.820 143.155 44.990 143.345 ;
        RECT 48.800 143.325 48.945 143.345 ;
        RECT 54.590 143.325 54.735 143.345 ;
        RECT 48.775 143.155 48.945 143.325 ;
        RECT 54.565 143.155 54.735 143.325 ;
        RECT 70.085 143.155 70.255 143.345 ;
        RECT 79.095 143.155 79.265 143.345 ;
        RECT 89.915 143.155 90.085 143.345 ;
        RECT 110.410 143.155 110.580 143.345 ;
        RECT 29.535 136.900 30.885 137.810 ;
        RECT 32.575 136.900 33.925 137.810 ;
        RECT 35.790 136.900 36.720 137.810 ;
        RECT 38.820 136.900 39.750 137.810 ;
        RECT 41.655 136.900 43.005 137.810 ;
        RECT 44.725 136.900 46.915 137.810 ;
        RECT 48.790 136.900 52.660 137.810 ;
        RECT 54.580 136.900 60.385 137.810 ;
        RECT 70.010 136.900 77.240 137.810 ;
        RECT 79.020 136.900 86.250 137.810 ;
        RECT 89.840 136.900 97.070 137.810 ;
        RECT 29.665 136.710 29.835 136.900 ;
        RECT 32.690 136.710 32.860 136.900 ;
        RECT 35.790 136.880 35.895 136.900 ;
        RECT 38.820 136.880 38.925 136.900 ;
        RECT 35.725 136.710 35.895 136.880 ;
        RECT 38.755 136.710 38.925 136.880 ;
        RECT 41.785 136.710 41.955 136.900 ;
        RECT 44.815 136.710 44.985 136.900 ;
        RECT 48.790 136.880 48.935 136.900 ;
        RECT 54.580 136.880 54.725 136.900 ;
        RECT 48.765 136.710 48.935 136.880 ;
        RECT 54.555 136.710 54.725 136.880 ;
        RECT 70.085 136.710 70.255 136.900 ;
        RECT 79.095 136.710 79.265 136.900 ;
        RECT 89.915 136.710 90.085 136.900 ;
        RECT 110.265 136.405 118.510 137.315 ;
        RECT 110.410 136.215 110.580 136.405 ;
        RECT 79.020 133.260 86.250 134.170 ;
        RECT 89.840 133.260 97.070 134.170 ;
        RECT 79.095 133.070 79.265 133.260 ;
        RECT 89.915 133.070 90.085 133.260 ;
        RECT 89.840 129.610 97.070 130.520 ;
        RECT 110.265 129.845 118.510 130.755 ;
        RECT 110.410 129.655 110.580 129.845 ;
        RECT 89.915 129.420 90.085 129.610 ;
        RECT 110.265 123.285 118.510 124.195 ;
        RECT 110.410 123.095 110.580 123.285 ;
        RECT 110.265 116.725 118.510 117.635 ;
        RECT 110.410 116.535 110.580 116.725 ;
        RECT 98.900 45.065 106.130 45.975 ;
        RECT 115.490 45.105 122.720 46.015 ;
        RECT 98.975 44.875 99.145 45.065 ;
        RECT 115.565 44.915 115.735 45.105 ;
        RECT 35.960 31.005 43.190 31.915 ;
        RECT 36.035 30.815 36.205 31.005 ;
        RECT 35.960 27.425 43.190 28.335 ;
        RECT 44.970 27.425 52.200 28.335 ;
        RECT 36.035 27.235 36.205 27.425 ;
        RECT 45.045 27.235 45.215 27.425 ;
        RECT 35.960 23.845 43.190 24.755 ;
        RECT 36.035 23.655 36.205 23.845 ;
        RECT 35.960 20.265 43.190 21.175 ;
        RECT 44.970 20.265 52.200 21.175 ;
        RECT 56.090 20.265 63.320 21.175 ;
        RECT 65.100 20.265 72.330 21.175 ;
        RECT 74.110 20.265 81.340 21.175 ;
        RECT 85.230 20.265 92.460 21.175 ;
        RECT 36.035 20.075 36.205 20.265 ;
        RECT 45.045 20.075 45.215 20.265 ;
        RECT 56.165 20.075 56.335 20.265 ;
        RECT 65.175 20.075 65.345 20.265 ;
        RECT 74.185 20.075 74.355 20.265 ;
        RECT 85.305 20.075 85.475 20.265 ;
        RECT 35.960 15.665 43.190 16.575 ;
        RECT 44.970 15.665 52.200 16.575 ;
        RECT 56.090 15.665 63.320 16.575 ;
        RECT 65.100 15.665 72.330 16.575 ;
        RECT 74.110 15.665 81.340 16.575 ;
        RECT 36.035 15.475 36.205 15.665 ;
        RECT 45.045 15.475 45.215 15.665 ;
        RECT 56.165 15.475 56.335 15.665 ;
        RECT 65.175 15.475 65.345 15.665 ;
        RECT 74.185 15.475 74.355 15.665 ;
      LAYER li1 ;
        RECT 110.350 164.585 110.605 165.385 ;
        RECT 111.275 164.585 111.500 165.385 ;
        RECT 112.170 164.585 112.340 165.385 ;
        RECT 113.010 164.585 113.180 165.385 ;
        RECT 113.850 164.585 114.020 165.385 ;
        RECT 114.710 165.215 118.455 165.385 ;
        RECT 114.710 164.585 114.960 165.215 ;
        RECT 110.350 164.415 111.105 164.585 ;
        RECT 111.275 164.415 114.960 164.585 ;
        RECT 115.130 164.545 115.460 165.045 ;
        RECT 115.630 164.715 115.800 165.215 ;
        RECT 115.970 164.545 116.300 165.045 ;
        RECT 116.470 164.715 116.640 165.215 ;
        RECT 116.810 164.545 117.140 165.045 ;
        RECT 117.310 164.715 117.480 165.215 ;
        RECT 117.650 164.545 117.980 165.045 ;
        RECT 118.150 164.715 118.455 165.215 ;
        RECT 110.775 164.245 111.105 164.415 ;
        RECT 115.130 164.375 118.455 164.545 ;
        RECT 110.775 163.915 114.735 164.245 ;
        RECT 114.905 163.915 118.060 164.205 ;
        RECT 110.775 163.745 111.105 163.915 ;
        RECT 118.230 163.745 118.455 164.375 ;
        RECT 110.350 163.575 111.105 163.745 ;
        RECT 111.275 163.575 114.960 163.745 ;
        RECT 110.350 163.175 110.605 163.575 ;
        RECT 111.275 163.175 111.545 163.575 ;
        RECT 112.215 163.175 112.385 163.575 ;
        RECT 113.055 163.175 113.225 163.575 ;
        RECT 113.895 163.175 114.065 163.575 ;
        RECT 114.745 163.370 114.960 163.575 ;
        RECT 115.130 163.540 118.455 163.745 ;
        RECT 114.745 163.175 118.455 163.370 ;
        RECT 110.350 158.025 110.605 158.825 ;
        RECT 111.275 158.025 111.500 158.825 ;
        RECT 112.170 158.025 112.340 158.825 ;
        RECT 113.010 158.025 113.180 158.825 ;
        RECT 113.850 158.025 114.020 158.825 ;
        RECT 114.710 158.655 118.455 158.825 ;
        RECT 114.710 158.025 114.960 158.655 ;
        RECT 110.350 157.855 111.105 158.025 ;
        RECT 111.275 157.855 114.960 158.025 ;
        RECT 115.130 157.985 115.460 158.485 ;
        RECT 115.630 158.155 115.800 158.655 ;
        RECT 115.970 157.985 116.300 158.485 ;
        RECT 116.470 158.155 116.640 158.655 ;
        RECT 116.810 157.985 117.140 158.485 ;
        RECT 117.310 158.155 117.480 158.655 ;
        RECT 117.650 157.985 117.980 158.485 ;
        RECT 118.150 158.155 118.455 158.655 ;
        RECT 110.775 157.685 111.105 157.855 ;
        RECT 115.130 157.815 118.455 157.985 ;
        RECT 110.775 157.355 114.735 157.685 ;
        RECT 114.905 157.355 118.060 157.645 ;
        RECT 110.775 157.185 111.105 157.355 ;
        RECT 118.230 157.185 118.455 157.815 ;
        RECT 110.350 157.015 111.105 157.185 ;
        RECT 111.275 157.015 114.960 157.185 ;
        RECT 110.350 156.615 110.605 157.015 ;
        RECT 111.275 156.615 111.545 157.015 ;
        RECT 112.215 156.615 112.385 157.015 ;
        RECT 113.055 156.615 113.225 157.015 ;
        RECT 113.895 156.615 114.065 157.015 ;
        RECT 114.745 156.810 114.960 157.015 ;
        RECT 115.130 156.980 118.455 157.185 ;
        RECT 114.745 156.615 118.455 156.810 ;
        RECT 90.350 152.185 90.680 152.985 ;
        RECT 91.190 152.185 91.520 152.985 ;
        RECT 92.030 152.185 92.360 152.985 ;
        RECT 92.870 152.185 93.200 152.985 ;
        RECT 93.710 152.185 94.040 152.985 ;
        RECT 94.550 152.185 94.880 152.985 ;
        RECT 95.390 152.185 95.720 152.985 ;
        RECT 96.230 152.185 96.560 152.985 ;
        RECT 90.350 152.015 96.560 152.185 ;
        RECT 89.855 151.595 95.295 151.835 ;
        RECT 96.230 151.425 96.560 152.015 ;
        RECT 90.350 151.235 96.560 151.425 ;
        RECT 110.350 151.465 110.605 152.265 ;
        RECT 111.275 151.465 111.500 152.265 ;
        RECT 112.170 151.465 112.340 152.265 ;
        RECT 113.010 151.465 113.180 152.265 ;
        RECT 113.850 151.465 114.020 152.265 ;
        RECT 114.710 152.095 118.455 152.265 ;
        RECT 114.710 151.465 114.960 152.095 ;
        RECT 110.350 151.295 111.105 151.465 ;
        RECT 111.275 151.295 114.960 151.465 ;
        RECT 115.130 151.425 115.460 151.925 ;
        RECT 115.630 151.595 115.800 152.095 ;
        RECT 115.970 151.425 116.300 151.925 ;
        RECT 116.470 151.595 116.640 152.095 ;
        RECT 116.810 151.425 117.140 151.925 ;
        RECT 117.310 151.595 117.480 152.095 ;
        RECT 117.650 151.425 117.980 151.925 ;
        RECT 118.150 151.595 118.455 152.095 ;
        RECT 90.350 150.775 90.680 151.235 ;
        RECT 91.190 150.775 91.520 151.235 ;
        RECT 92.030 150.775 92.360 151.235 ;
        RECT 92.870 150.775 93.200 151.235 ;
        RECT 93.710 150.775 94.040 151.235 ;
        RECT 94.550 150.775 94.880 151.235 ;
        RECT 95.390 150.775 95.720 151.235 ;
        RECT 96.230 150.775 96.560 151.235 ;
        RECT 110.775 151.125 111.105 151.295 ;
        RECT 115.130 151.255 118.455 151.425 ;
        RECT 110.775 150.795 114.735 151.125 ;
        RECT 114.905 150.795 118.060 151.085 ;
        RECT 110.775 150.625 111.105 150.795 ;
        RECT 118.230 150.625 118.455 151.255 ;
        RECT 110.350 150.455 111.105 150.625 ;
        RECT 111.275 150.455 114.960 150.625 ;
        RECT 110.350 150.055 110.605 150.455 ;
        RECT 111.275 150.055 111.545 150.455 ;
        RECT 112.215 150.055 112.385 150.455 ;
        RECT 113.055 150.055 113.225 150.455 ;
        RECT 113.895 150.055 114.065 150.455 ;
        RECT 114.745 150.250 114.960 150.455 ;
        RECT 115.130 150.420 118.455 150.625 ;
        RECT 114.745 150.055 118.455 150.250 ;
        RECT 79.530 148.545 79.860 149.345 ;
        RECT 80.370 148.545 80.700 149.345 ;
        RECT 81.210 148.545 81.540 149.345 ;
        RECT 82.050 148.545 82.380 149.345 ;
        RECT 82.890 148.545 83.220 149.345 ;
        RECT 83.730 148.545 84.060 149.345 ;
        RECT 84.570 148.545 84.900 149.345 ;
        RECT 85.410 148.545 85.740 149.345 ;
        RECT 79.530 148.375 85.740 148.545 ;
        RECT 90.350 148.545 90.680 149.345 ;
        RECT 91.190 148.545 91.520 149.345 ;
        RECT 92.030 148.545 92.360 149.345 ;
        RECT 92.870 148.545 93.200 149.345 ;
        RECT 93.710 148.545 94.040 149.345 ;
        RECT 94.550 148.545 94.880 149.345 ;
        RECT 95.390 148.545 95.720 149.345 ;
        RECT 96.230 148.545 96.560 149.345 ;
        RECT 90.350 148.375 96.560 148.545 ;
        RECT 79.035 147.955 84.475 148.195 ;
        RECT 85.410 147.785 85.740 148.375 ;
        RECT 89.855 147.955 95.295 148.195 ;
        RECT 96.230 147.785 96.560 148.375 ;
        RECT 79.530 147.595 85.740 147.785 ;
        RECT 79.530 147.135 79.860 147.595 ;
        RECT 80.370 147.135 80.700 147.595 ;
        RECT 81.210 147.135 81.540 147.595 ;
        RECT 82.050 147.135 82.380 147.595 ;
        RECT 82.890 147.135 83.220 147.595 ;
        RECT 83.730 147.135 84.060 147.595 ;
        RECT 84.570 147.135 84.900 147.595 ;
        RECT 85.410 147.135 85.740 147.595 ;
        RECT 90.350 147.595 96.560 147.785 ;
        RECT 90.350 147.135 90.680 147.595 ;
        RECT 91.190 147.135 91.520 147.595 ;
        RECT 92.030 147.135 92.360 147.595 ;
        RECT 92.870 147.135 93.200 147.595 ;
        RECT 93.710 147.135 94.040 147.595 ;
        RECT 94.550 147.135 94.880 147.595 ;
        RECT 95.390 147.135 95.720 147.595 ;
        RECT 96.230 147.135 96.560 147.595 ;
        RECT 33.085 144.725 33.415 145.705 ;
        RECT 36.305 144.725 36.635 145.705 ;
        RECT 39.335 144.725 39.665 145.705 ;
        RECT 42.170 144.725 42.500 145.705 ;
        RECT 45.240 144.905 45.570 145.705 ;
        RECT 46.080 144.925 46.410 145.705 ;
        RECT 46.080 144.905 46.845 144.925 ;
        RECT 49.310 144.905 49.640 145.705 ;
        RECT 50.150 144.905 50.480 145.705 ;
        RECT 50.990 144.905 51.320 145.705 ;
        RECT 51.830 144.905 52.160 145.705 ;
        RECT 55.100 144.905 55.430 145.705 ;
        RECT 55.940 144.905 56.270 145.705 ;
        RECT 56.780 144.905 57.110 145.705 ;
        RECT 57.620 144.905 57.950 145.705 ;
        RECT 58.460 144.905 58.790 145.705 ;
        RECT 59.300 144.905 59.630 145.705 ;
        RECT 70.520 144.905 70.850 145.705 ;
        RECT 71.360 144.905 71.690 145.705 ;
        RECT 72.200 144.905 72.530 145.705 ;
        RECT 73.040 144.905 73.370 145.705 ;
        RECT 73.880 144.905 74.210 145.705 ;
        RECT 74.720 144.905 75.050 145.705 ;
        RECT 75.560 144.905 75.890 145.705 ;
        RECT 76.400 144.905 76.730 145.705 ;
        RECT 45.240 144.735 46.845 144.905 ;
        RECT 33.150 144.125 33.320 144.725 ;
        RECT 33.490 144.315 33.825 144.565 ;
        RECT 35.905 144.315 36.235 144.555 ;
        RECT 36.405 144.125 36.635 144.725 ;
        RECT 38.935 144.315 39.265 144.555 ;
        RECT 39.435 144.125 39.665 144.725 ;
        RECT 41.750 144.315 42.080 144.565 ;
        RECT 42.250 144.125 42.500 144.725 ;
        RECT 44.780 144.315 46.410 144.565 ;
        RECT 46.580 144.145 46.845 144.735 ;
        RECT 33.150 143.495 33.845 144.125 ;
        RECT 36.305 143.495 36.635 144.125 ;
        RECT 39.335 143.495 39.665 144.125 ;
        RECT 42.170 143.495 42.500 144.125 ;
        RECT 45.240 143.965 46.845 144.145 ;
        RECT 48.715 144.735 52.685 144.905 ;
        RECT 48.715 144.145 49.060 144.735 ;
        RECT 49.310 144.315 52.165 144.565 ;
        RECT 52.365 144.145 52.685 144.735 ;
        RECT 45.240 143.495 45.570 143.965 ;
        RECT 46.080 143.495 46.410 143.965 ;
        RECT 48.715 143.955 52.685 144.145 ;
        RECT 54.505 144.735 60.315 144.905 ;
        RECT 70.520 144.735 76.730 144.905 ;
        RECT 79.530 144.905 79.860 145.705 ;
        RECT 80.370 144.905 80.700 145.705 ;
        RECT 81.210 144.905 81.540 145.705 ;
        RECT 82.050 144.905 82.380 145.705 ;
        RECT 82.890 144.905 83.220 145.705 ;
        RECT 83.730 144.905 84.060 145.705 ;
        RECT 84.570 144.905 84.900 145.705 ;
        RECT 85.410 144.905 85.740 145.705 ;
        RECT 79.530 144.735 85.740 144.905 ;
        RECT 90.350 144.905 90.680 145.705 ;
        RECT 91.190 144.905 91.520 145.705 ;
        RECT 92.030 144.905 92.360 145.705 ;
        RECT 92.870 144.905 93.200 145.705 ;
        RECT 93.710 144.905 94.040 145.705 ;
        RECT 94.550 144.905 94.880 145.705 ;
        RECT 95.390 144.905 95.720 145.705 ;
        RECT 96.230 144.905 96.560 145.705 ;
        RECT 90.350 144.735 96.560 144.905 ;
        RECT 110.350 144.905 110.605 145.705 ;
        RECT 111.275 144.905 111.500 145.705 ;
        RECT 112.170 144.905 112.340 145.705 ;
        RECT 113.010 144.905 113.180 145.705 ;
        RECT 113.850 144.905 114.020 145.705 ;
        RECT 114.710 145.535 118.455 145.705 ;
        RECT 114.710 144.905 114.960 145.535 ;
        RECT 110.350 144.735 111.105 144.905 ;
        RECT 111.275 144.735 114.960 144.905 ;
        RECT 115.130 144.865 115.460 145.365 ;
        RECT 115.630 145.035 115.800 145.535 ;
        RECT 115.970 144.865 116.300 145.365 ;
        RECT 116.470 145.035 116.640 145.535 ;
        RECT 116.810 144.865 117.140 145.365 ;
        RECT 117.310 145.035 117.480 145.535 ;
        RECT 117.650 144.865 117.980 145.365 ;
        RECT 118.150 145.035 118.455 145.535 ;
        RECT 54.505 144.145 54.930 144.735 ;
        RECT 55.100 144.315 59.690 144.565 ;
        RECT 59.965 144.145 60.315 144.735 ;
        RECT 70.025 144.315 75.465 144.555 ;
        RECT 76.400 144.145 76.730 144.735 ;
        RECT 79.035 144.315 84.475 144.555 ;
        RECT 85.410 144.145 85.740 144.735 ;
        RECT 89.855 144.315 95.295 144.555 ;
        RECT 96.230 144.145 96.560 144.735 ;
        RECT 54.505 143.955 60.315 144.145 ;
        RECT 70.520 143.955 76.730 144.145 ;
        RECT 49.310 143.495 49.640 143.955 ;
        RECT 50.150 143.495 50.480 143.955 ;
        RECT 50.990 143.495 51.320 143.955 ;
        RECT 51.830 143.495 52.160 143.955 ;
        RECT 55.100 143.495 55.430 143.955 ;
        RECT 55.940 143.495 56.270 143.955 ;
        RECT 56.780 143.495 57.110 143.955 ;
        RECT 57.620 143.495 57.950 143.955 ;
        RECT 58.460 143.495 58.790 143.955 ;
        RECT 59.300 143.495 59.630 143.955 ;
        RECT 70.520 143.495 70.850 143.955 ;
        RECT 71.360 143.495 71.690 143.955 ;
        RECT 72.200 143.495 72.530 143.955 ;
        RECT 73.040 143.495 73.370 143.955 ;
        RECT 73.880 143.495 74.210 143.955 ;
        RECT 74.720 143.495 75.050 143.955 ;
        RECT 75.560 143.495 75.890 143.955 ;
        RECT 76.400 143.495 76.730 143.955 ;
        RECT 79.530 143.955 85.740 144.145 ;
        RECT 79.530 143.495 79.860 143.955 ;
        RECT 80.370 143.495 80.700 143.955 ;
        RECT 81.210 143.495 81.540 143.955 ;
        RECT 82.050 143.495 82.380 143.955 ;
        RECT 82.890 143.495 83.220 143.955 ;
        RECT 83.730 143.495 84.060 143.955 ;
        RECT 84.570 143.495 84.900 143.955 ;
        RECT 85.410 143.495 85.740 143.955 ;
        RECT 90.350 143.955 96.560 144.145 ;
        RECT 110.775 144.565 111.105 144.735 ;
        RECT 115.130 144.695 118.455 144.865 ;
        RECT 110.775 144.235 114.735 144.565 ;
        RECT 114.905 144.235 118.060 144.525 ;
        RECT 110.775 144.065 111.105 144.235 ;
        RECT 118.230 144.065 118.455 144.695 ;
        RECT 90.350 143.495 90.680 143.955 ;
        RECT 91.190 143.495 91.520 143.955 ;
        RECT 92.030 143.495 92.360 143.955 ;
        RECT 92.870 143.495 93.200 143.955 ;
        RECT 93.710 143.495 94.040 143.955 ;
        RECT 94.550 143.495 94.880 143.955 ;
        RECT 95.390 143.495 95.720 143.955 ;
        RECT 96.230 143.495 96.560 143.955 ;
        RECT 110.350 143.895 111.105 144.065 ;
        RECT 111.275 143.895 114.960 144.065 ;
        RECT 110.350 143.495 110.605 143.895 ;
        RECT 111.275 143.495 111.545 143.895 ;
        RECT 112.215 143.495 112.385 143.895 ;
        RECT 113.055 143.495 113.225 143.895 ;
        RECT 113.895 143.495 114.065 143.895 ;
        RECT 114.745 143.690 114.960 143.895 ;
        RECT 115.130 143.860 118.455 144.065 ;
        RECT 114.745 143.495 118.455 143.690 ;
        RECT 30.045 138.280 30.375 139.260 ;
        RECT 33.085 138.280 33.415 139.260 ;
        RECT 36.300 138.280 36.630 139.260 ;
        RECT 39.330 138.280 39.660 139.260 ;
        RECT 42.165 138.280 42.495 139.260 ;
        RECT 45.235 138.460 45.565 139.260 ;
        RECT 46.075 138.480 46.405 139.260 ;
        RECT 46.075 138.460 46.840 138.480 ;
        RECT 49.300 138.460 49.630 139.260 ;
        RECT 50.140 138.460 50.470 139.260 ;
        RECT 50.980 138.460 51.310 139.260 ;
        RECT 51.820 138.460 52.150 139.260 ;
        RECT 55.090 138.460 55.420 139.260 ;
        RECT 55.930 138.460 56.260 139.260 ;
        RECT 56.770 138.460 57.100 139.260 ;
        RECT 57.610 138.460 57.940 139.260 ;
        RECT 58.450 138.460 58.780 139.260 ;
        RECT 59.290 138.460 59.620 139.260 ;
        RECT 70.520 138.460 70.850 139.260 ;
        RECT 71.360 138.460 71.690 139.260 ;
        RECT 72.200 138.460 72.530 139.260 ;
        RECT 73.040 138.460 73.370 139.260 ;
        RECT 73.880 138.460 74.210 139.260 ;
        RECT 74.720 138.460 75.050 139.260 ;
        RECT 75.560 138.460 75.890 139.260 ;
        RECT 76.400 138.460 76.730 139.260 ;
        RECT 45.235 138.290 46.840 138.460 ;
        RECT 30.125 137.680 30.375 138.280 ;
        RECT 32.645 137.850 32.980 138.120 ;
        RECT 30.045 137.050 30.375 137.680 ;
        RECT 33.150 137.680 33.320 138.280 ;
        RECT 33.490 137.870 33.825 138.120 ;
        RECT 35.900 137.870 36.230 138.110 ;
        RECT 36.400 137.680 36.630 138.280 ;
        RECT 38.930 137.870 39.260 138.110 ;
        RECT 39.430 137.680 39.660 138.280 ;
        RECT 41.745 137.870 42.075 138.120 ;
        RECT 42.245 137.680 42.495 138.280 ;
        RECT 44.775 137.870 46.405 138.120 ;
        RECT 46.575 137.700 46.840 138.290 ;
        RECT 33.150 137.050 33.845 137.680 ;
        RECT 36.300 137.050 36.630 137.680 ;
        RECT 39.330 137.050 39.660 137.680 ;
        RECT 42.165 137.050 42.495 137.680 ;
        RECT 45.235 137.520 46.840 137.700 ;
        RECT 48.705 138.290 52.675 138.460 ;
        RECT 48.705 137.700 49.050 138.290 ;
        RECT 49.300 137.870 52.155 138.120 ;
        RECT 52.355 137.700 52.675 138.290 ;
        RECT 45.235 137.050 45.565 137.520 ;
        RECT 46.075 137.050 46.405 137.520 ;
        RECT 48.705 137.510 52.675 137.700 ;
        RECT 54.495 138.290 60.305 138.460 ;
        RECT 70.520 138.290 76.730 138.460 ;
        RECT 79.530 138.460 79.860 139.260 ;
        RECT 80.370 138.460 80.700 139.260 ;
        RECT 81.210 138.460 81.540 139.260 ;
        RECT 82.050 138.460 82.380 139.260 ;
        RECT 82.890 138.460 83.220 139.260 ;
        RECT 83.730 138.460 84.060 139.260 ;
        RECT 84.570 138.460 84.900 139.260 ;
        RECT 85.410 138.460 85.740 139.260 ;
        RECT 79.530 138.290 85.740 138.460 ;
        RECT 90.350 138.460 90.680 139.260 ;
        RECT 91.190 138.460 91.520 139.260 ;
        RECT 92.030 138.460 92.360 139.260 ;
        RECT 92.870 138.460 93.200 139.260 ;
        RECT 93.710 138.460 94.040 139.260 ;
        RECT 94.550 138.460 94.880 139.260 ;
        RECT 95.390 138.460 95.720 139.260 ;
        RECT 96.230 138.460 96.560 139.260 ;
        RECT 90.350 138.290 96.560 138.460 ;
        RECT 54.495 137.700 54.920 138.290 ;
        RECT 55.090 137.870 59.680 138.120 ;
        RECT 59.955 137.700 60.305 138.290 ;
        RECT 70.025 137.870 75.465 138.110 ;
        RECT 76.400 137.700 76.730 138.290 ;
        RECT 79.035 137.870 84.475 138.110 ;
        RECT 85.410 137.700 85.740 138.290 ;
        RECT 89.855 137.870 95.295 138.110 ;
        RECT 96.230 137.700 96.560 138.290 ;
        RECT 110.350 137.965 110.605 138.765 ;
        RECT 111.275 137.965 111.500 138.765 ;
        RECT 112.170 137.965 112.340 138.765 ;
        RECT 113.010 137.965 113.180 138.765 ;
        RECT 113.850 137.965 114.020 138.765 ;
        RECT 114.710 138.595 118.455 138.765 ;
        RECT 114.710 137.965 114.960 138.595 ;
        RECT 110.350 137.795 111.105 137.965 ;
        RECT 111.275 137.795 114.960 137.965 ;
        RECT 115.130 137.925 115.460 138.425 ;
        RECT 115.630 138.095 115.800 138.595 ;
        RECT 115.970 137.925 116.300 138.425 ;
        RECT 116.470 138.095 116.640 138.595 ;
        RECT 116.810 137.925 117.140 138.425 ;
        RECT 117.310 138.095 117.480 138.595 ;
        RECT 117.650 137.925 117.980 138.425 ;
        RECT 118.150 138.095 118.455 138.595 ;
        RECT 54.495 137.510 60.305 137.700 ;
        RECT 70.520 137.510 76.730 137.700 ;
        RECT 49.300 137.050 49.630 137.510 ;
        RECT 50.140 137.050 50.470 137.510 ;
        RECT 50.980 137.050 51.310 137.510 ;
        RECT 51.820 137.050 52.150 137.510 ;
        RECT 55.090 137.050 55.420 137.510 ;
        RECT 55.930 137.050 56.260 137.510 ;
        RECT 56.770 137.050 57.100 137.510 ;
        RECT 57.610 137.050 57.940 137.510 ;
        RECT 58.450 137.050 58.780 137.510 ;
        RECT 59.290 137.050 59.620 137.510 ;
        RECT 70.520 137.050 70.850 137.510 ;
        RECT 71.360 137.050 71.690 137.510 ;
        RECT 72.200 137.050 72.530 137.510 ;
        RECT 73.040 137.050 73.370 137.510 ;
        RECT 73.880 137.050 74.210 137.510 ;
        RECT 74.720 137.050 75.050 137.510 ;
        RECT 75.560 137.050 75.890 137.510 ;
        RECT 76.400 137.050 76.730 137.510 ;
        RECT 79.530 137.510 85.740 137.700 ;
        RECT 79.530 137.050 79.860 137.510 ;
        RECT 80.370 137.050 80.700 137.510 ;
        RECT 81.210 137.050 81.540 137.510 ;
        RECT 82.050 137.050 82.380 137.510 ;
        RECT 82.890 137.050 83.220 137.510 ;
        RECT 83.730 137.050 84.060 137.510 ;
        RECT 84.570 137.050 84.900 137.510 ;
        RECT 85.410 137.050 85.740 137.510 ;
        RECT 90.350 137.510 96.560 137.700 ;
        RECT 90.350 137.050 90.680 137.510 ;
        RECT 91.190 137.050 91.520 137.510 ;
        RECT 92.030 137.050 92.360 137.510 ;
        RECT 92.870 137.050 93.200 137.510 ;
        RECT 93.710 137.050 94.040 137.510 ;
        RECT 94.550 137.050 94.880 137.510 ;
        RECT 95.390 137.050 95.720 137.510 ;
        RECT 96.230 137.050 96.560 137.510 ;
        RECT 110.775 137.625 111.105 137.795 ;
        RECT 115.130 137.755 118.455 137.925 ;
        RECT 110.775 137.295 114.735 137.625 ;
        RECT 114.905 137.295 118.060 137.585 ;
        RECT 110.775 137.125 111.105 137.295 ;
        RECT 118.230 137.125 118.455 137.755 ;
        RECT 110.350 136.955 111.105 137.125 ;
        RECT 111.275 136.955 114.960 137.125 ;
        RECT 110.350 136.555 110.605 136.955 ;
        RECT 111.275 136.555 111.545 136.955 ;
        RECT 112.215 136.555 112.385 136.955 ;
        RECT 113.055 136.555 113.225 136.955 ;
        RECT 113.895 136.555 114.065 136.955 ;
        RECT 114.745 136.750 114.960 136.955 ;
        RECT 115.130 136.920 118.455 137.125 ;
        RECT 114.745 136.555 118.455 136.750 ;
        RECT 79.530 134.820 79.860 135.620 ;
        RECT 80.370 134.820 80.700 135.620 ;
        RECT 81.210 134.820 81.540 135.620 ;
        RECT 82.050 134.820 82.380 135.620 ;
        RECT 82.890 134.820 83.220 135.620 ;
        RECT 83.730 134.820 84.060 135.620 ;
        RECT 84.570 134.820 84.900 135.620 ;
        RECT 85.410 134.820 85.740 135.620 ;
        RECT 79.530 134.650 85.740 134.820 ;
        RECT 90.350 134.820 90.680 135.620 ;
        RECT 91.190 134.820 91.520 135.620 ;
        RECT 92.030 134.820 92.360 135.620 ;
        RECT 92.870 134.820 93.200 135.620 ;
        RECT 93.710 134.820 94.040 135.620 ;
        RECT 94.550 134.820 94.880 135.620 ;
        RECT 95.390 134.820 95.720 135.620 ;
        RECT 96.230 134.820 96.560 135.620 ;
        RECT 90.350 134.650 96.560 134.820 ;
        RECT 79.035 134.230 84.475 134.470 ;
        RECT 85.410 134.060 85.740 134.650 ;
        RECT 89.855 134.230 95.295 134.470 ;
        RECT 96.230 134.060 96.560 134.650 ;
        RECT 79.530 133.870 85.740 134.060 ;
        RECT 79.530 133.410 79.860 133.870 ;
        RECT 80.370 133.410 80.700 133.870 ;
        RECT 81.210 133.410 81.540 133.870 ;
        RECT 82.050 133.410 82.380 133.870 ;
        RECT 82.890 133.410 83.220 133.870 ;
        RECT 83.730 133.410 84.060 133.870 ;
        RECT 84.570 133.410 84.900 133.870 ;
        RECT 85.410 133.410 85.740 133.870 ;
        RECT 90.350 133.870 96.560 134.060 ;
        RECT 90.350 133.410 90.680 133.870 ;
        RECT 91.190 133.410 91.520 133.870 ;
        RECT 92.030 133.410 92.360 133.870 ;
        RECT 92.870 133.410 93.200 133.870 ;
        RECT 93.710 133.410 94.040 133.870 ;
        RECT 94.550 133.410 94.880 133.870 ;
        RECT 95.390 133.410 95.720 133.870 ;
        RECT 96.230 133.410 96.560 133.870 ;
        RECT 90.350 131.170 90.680 131.970 ;
        RECT 91.190 131.170 91.520 131.970 ;
        RECT 92.030 131.170 92.360 131.970 ;
        RECT 92.870 131.170 93.200 131.970 ;
        RECT 93.710 131.170 94.040 131.970 ;
        RECT 94.550 131.170 94.880 131.970 ;
        RECT 95.390 131.170 95.720 131.970 ;
        RECT 96.230 131.170 96.560 131.970 ;
        RECT 110.350 131.405 110.605 132.205 ;
        RECT 111.275 131.405 111.500 132.205 ;
        RECT 112.170 131.405 112.340 132.205 ;
        RECT 113.010 131.405 113.180 132.205 ;
        RECT 113.850 131.405 114.020 132.205 ;
        RECT 114.710 132.035 118.455 132.205 ;
        RECT 114.710 131.405 114.960 132.035 ;
        RECT 110.350 131.235 111.105 131.405 ;
        RECT 111.275 131.235 114.960 131.405 ;
        RECT 115.130 131.365 115.460 131.865 ;
        RECT 115.630 131.535 115.800 132.035 ;
        RECT 115.970 131.365 116.300 131.865 ;
        RECT 116.470 131.535 116.640 132.035 ;
        RECT 116.810 131.365 117.140 131.865 ;
        RECT 117.310 131.535 117.480 132.035 ;
        RECT 117.650 131.365 117.980 131.865 ;
        RECT 118.150 131.535 118.455 132.035 ;
        RECT 90.350 131.000 96.560 131.170 ;
        RECT 89.855 130.580 95.295 130.820 ;
        RECT 96.230 130.410 96.560 131.000 ;
        RECT 110.775 131.065 111.105 131.235 ;
        RECT 115.130 131.195 118.455 131.365 ;
        RECT 110.775 130.735 114.735 131.065 ;
        RECT 114.905 130.735 118.060 131.025 ;
        RECT 110.775 130.565 111.105 130.735 ;
        RECT 118.230 130.565 118.455 131.195 ;
        RECT 90.350 130.220 96.560 130.410 ;
        RECT 90.350 129.760 90.680 130.220 ;
        RECT 91.190 129.760 91.520 130.220 ;
        RECT 92.030 129.760 92.360 130.220 ;
        RECT 92.870 129.760 93.200 130.220 ;
        RECT 93.710 129.760 94.040 130.220 ;
        RECT 94.550 129.760 94.880 130.220 ;
        RECT 95.390 129.760 95.720 130.220 ;
        RECT 96.230 129.760 96.560 130.220 ;
        RECT 110.350 130.395 111.105 130.565 ;
        RECT 111.275 130.395 114.960 130.565 ;
        RECT 110.350 129.995 110.605 130.395 ;
        RECT 111.275 129.995 111.545 130.395 ;
        RECT 112.215 129.995 112.385 130.395 ;
        RECT 113.055 129.995 113.225 130.395 ;
        RECT 113.895 129.995 114.065 130.395 ;
        RECT 114.745 130.190 114.960 130.395 ;
        RECT 115.130 130.360 118.455 130.565 ;
        RECT 114.745 129.995 118.455 130.190 ;
        RECT 110.350 124.845 110.605 125.645 ;
        RECT 111.275 124.845 111.500 125.645 ;
        RECT 112.170 124.845 112.340 125.645 ;
        RECT 113.010 124.845 113.180 125.645 ;
        RECT 113.850 124.845 114.020 125.645 ;
        RECT 114.710 125.475 118.455 125.645 ;
        RECT 114.710 124.845 114.960 125.475 ;
        RECT 110.350 124.675 111.105 124.845 ;
        RECT 111.275 124.675 114.960 124.845 ;
        RECT 115.130 124.805 115.460 125.305 ;
        RECT 115.630 124.975 115.800 125.475 ;
        RECT 115.970 124.805 116.300 125.305 ;
        RECT 116.470 124.975 116.640 125.475 ;
        RECT 116.810 124.805 117.140 125.305 ;
        RECT 117.310 124.975 117.480 125.475 ;
        RECT 117.650 124.805 117.980 125.305 ;
        RECT 118.150 124.975 118.455 125.475 ;
        RECT 110.775 124.505 111.105 124.675 ;
        RECT 115.130 124.635 118.455 124.805 ;
        RECT 110.775 124.175 114.735 124.505 ;
        RECT 114.905 124.175 118.060 124.465 ;
        RECT 110.775 124.005 111.105 124.175 ;
        RECT 118.230 124.005 118.455 124.635 ;
        RECT 110.350 123.835 111.105 124.005 ;
        RECT 111.275 123.835 114.960 124.005 ;
        RECT 110.350 123.435 110.605 123.835 ;
        RECT 111.275 123.435 111.545 123.835 ;
        RECT 112.215 123.435 112.385 123.835 ;
        RECT 113.055 123.435 113.225 123.835 ;
        RECT 113.895 123.435 114.065 123.835 ;
        RECT 114.745 123.630 114.960 123.835 ;
        RECT 115.130 123.800 118.455 124.005 ;
        RECT 114.745 123.435 118.455 123.630 ;
        RECT 110.350 118.285 110.605 119.085 ;
        RECT 111.275 118.285 111.500 119.085 ;
        RECT 112.170 118.285 112.340 119.085 ;
        RECT 113.010 118.285 113.180 119.085 ;
        RECT 113.850 118.285 114.020 119.085 ;
        RECT 114.710 118.915 118.455 119.085 ;
        RECT 114.710 118.285 114.960 118.915 ;
        RECT 110.350 118.115 111.105 118.285 ;
        RECT 111.275 118.115 114.960 118.285 ;
        RECT 115.130 118.245 115.460 118.745 ;
        RECT 115.630 118.415 115.800 118.915 ;
        RECT 115.970 118.245 116.300 118.745 ;
        RECT 116.470 118.415 116.640 118.915 ;
        RECT 116.810 118.245 117.140 118.745 ;
        RECT 117.310 118.415 117.480 118.915 ;
        RECT 117.650 118.245 117.980 118.745 ;
        RECT 118.150 118.415 118.455 118.915 ;
        RECT 110.775 117.945 111.105 118.115 ;
        RECT 115.130 118.075 118.455 118.245 ;
        RECT 110.775 117.615 114.735 117.945 ;
        RECT 114.905 117.615 118.060 117.905 ;
        RECT 110.775 117.445 111.105 117.615 ;
        RECT 118.230 117.445 118.455 118.075 ;
        RECT 110.350 117.275 111.105 117.445 ;
        RECT 111.275 117.275 114.960 117.445 ;
        RECT 110.350 116.875 110.605 117.275 ;
        RECT 111.275 116.875 111.545 117.275 ;
        RECT 112.215 116.875 112.385 117.275 ;
        RECT 113.055 116.875 113.225 117.275 ;
        RECT 113.895 116.875 114.065 117.275 ;
        RECT 114.745 117.070 114.960 117.275 ;
        RECT 115.130 117.240 118.455 117.445 ;
        RECT 114.745 116.875 118.455 117.070 ;
        RECT 99.410 46.625 99.740 47.425 ;
        RECT 100.250 46.625 100.580 47.425 ;
        RECT 101.090 46.625 101.420 47.425 ;
        RECT 101.930 46.625 102.260 47.425 ;
        RECT 102.770 46.625 103.100 47.425 ;
        RECT 103.610 46.625 103.940 47.425 ;
        RECT 104.450 46.625 104.780 47.425 ;
        RECT 105.290 46.625 105.620 47.425 ;
        RECT 99.410 46.455 105.620 46.625 ;
        RECT 116.000 46.665 116.330 47.465 ;
        RECT 116.840 46.665 117.170 47.465 ;
        RECT 117.680 46.665 118.010 47.465 ;
        RECT 118.520 46.665 118.850 47.465 ;
        RECT 119.360 46.665 119.690 47.465 ;
        RECT 120.200 46.665 120.530 47.465 ;
        RECT 121.040 46.665 121.370 47.465 ;
        RECT 121.880 46.665 122.210 47.465 ;
        RECT 116.000 46.495 122.210 46.665 ;
        RECT 98.915 46.035 104.355 46.275 ;
        RECT 105.290 45.865 105.620 46.455 ;
        RECT 115.505 46.075 120.945 46.315 ;
        RECT 121.880 45.905 122.210 46.495 ;
        RECT 99.410 45.675 105.620 45.865 ;
        RECT 99.410 45.215 99.740 45.675 ;
        RECT 100.250 45.215 100.580 45.675 ;
        RECT 101.090 45.215 101.420 45.675 ;
        RECT 101.930 45.215 102.260 45.675 ;
        RECT 102.770 45.215 103.100 45.675 ;
        RECT 103.610 45.215 103.940 45.675 ;
        RECT 104.450 45.215 104.780 45.675 ;
        RECT 105.290 45.215 105.620 45.675 ;
        RECT 116.000 45.715 122.210 45.905 ;
        RECT 116.000 45.255 116.330 45.715 ;
        RECT 116.840 45.255 117.170 45.715 ;
        RECT 117.680 45.255 118.010 45.715 ;
        RECT 118.520 45.255 118.850 45.715 ;
        RECT 119.360 45.255 119.690 45.715 ;
        RECT 120.200 45.255 120.530 45.715 ;
        RECT 121.040 45.255 121.370 45.715 ;
        RECT 121.880 45.255 122.210 45.715 ;
        RECT 36.470 32.565 36.800 33.365 ;
        RECT 37.310 32.565 37.640 33.365 ;
        RECT 38.150 32.565 38.480 33.365 ;
        RECT 38.990 32.565 39.320 33.365 ;
        RECT 39.830 32.565 40.160 33.365 ;
        RECT 40.670 32.565 41.000 33.365 ;
        RECT 41.510 32.565 41.840 33.365 ;
        RECT 42.350 32.565 42.680 33.365 ;
        RECT 36.470 32.395 42.680 32.565 ;
        RECT 42.350 31.805 42.680 32.395 ;
        RECT 36.470 31.615 42.680 31.805 ;
        RECT 36.470 31.155 36.800 31.615 ;
        RECT 37.310 31.155 37.640 31.615 ;
        RECT 38.150 31.155 38.480 31.615 ;
        RECT 38.990 31.155 39.320 31.615 ;
        RECT 39.830 31.155 40.160 31.615 ;
        RECT 40.670 31.155 41.000 31.615 ;
        RECT 41.510 31.155 41.840 31.615 ;
        RECT 42.350 31.155 42.680 31.615 ;
        RECT 36.470 28.985 36.800 29.785 ;
        RECT 37.310 28.985 37.640 29.785 ;
        RECT 38.150 28.985 38.480 29.785 ;
        RECT 38.990 28.985 39.320 29.785 ;
        RECT 39.830 28.985 40.160 29.785 ;
        RECT 40.670 28.985 41.000 29.785 ;
        RECT 41.510 28.985 41.840 29.785 ;
        RECT 42.350 28.985 42.680 29.785 ;
        RECT 36.470 28.815 42.680 28.985 ;
        RECT 35.975 28.395 41.415 28.635 ;
        RECT 42.350 28.225 42.680 28.815 ;
        RECT 44.985 28.395 50.425 28.635 ;
        RECT 36.470 28.035 42.680 28.225 ;
        RECT 36.470 27.575 36.800 28.035 ;
        RECT 37.310 27.575 37.640 28.035 ;
        RECT 38.150 27.575 38.480 28.035 ;
        RECT 38.990 27.575 39.320 28.035 ;
        RECT 39.830 27.575 40.160 28.035 ;
        RECT 40.670 27.575 41.000 28.035 ;
        RECT 41.510 27.575 41.840 28.035 ;
        RECT 42.350 27.575 42.680 28.035 ;
        RECT 36.470 25.405 36.800 26.205 ;
        RECT 37.310 25.405 37.640 26.205 ;
        RECT 38.150 25.405 38.480 26.205 ;
        RECT 38.990 25.405 39.320 26.205 ;
        RECT 39.830 25.405 40.160 26.205 ;
        RECT 40.670 25.405 41.000 26.205 ;
        RECT 41.510 25.405 41.840 26.205 ;
        RECT 42.350 25.405 42.680 26.205 ;
        RECT 36.470 25.235 42.680 25.405 ;
        RECT 35.975 24.815 41.415 25.055 ;
        RECT 42.350 24.645 42.680 25.235 ;
        RECT 36.470 24.455 42.680 24.645 ;
        RECT 36.470 23.995 36.800 24.455 ;
        RECT 37.310 23.995 37.640 24.455 ;
        RECT 38.150 23.995 38.480 24.455 ;
        RECT 38.990 23.995 39.320 24.455 ;
        RECT 39.830 23.995 40.160 24.455 ;
        RECT 40.670 23.995 41.000 24.455 ;
        RECT 41.510 23.995 41.840 24.455 ;
        RECT 42.350 23.995 42.680 24.455 ;
        RECT 36.470 21.825 36.800 22.625 ;
        RECT 37.310 21.825 37.640 22.625 ;
        RECT 38.150 21.825 38.480 22.625 ;
        RECT 38.990 21.825 39.320 22.625 ;
        RECT 39.830 21.825 40.160 22.625 ;
        RECT 40.670 21.825 41.000 22.625 ;
        RECT 41.510 21.825 41.840 22.625 ;
        RECT 42.350 21.825 42.680 22.625 ;
        RECT 36.470 21.655 42.680 21.825 ;
        RECT 45.480 21.825 45.810 22.625 ;
        RECT 46.320 21.825 46.650 22.625 ;
        RECT 47.160 21.825 47.490 22.625 ;
        RECT 48.000 21.825 48.330 22.625 ;
        RECT 48.840 21.825 49.170 22.625 ;
        RECT 49.680 21.825 50.010 22.625 ;
        RECT 50.520 21.825 50.850 22.625 ;
        RECT 51.360 21.825 51.690 22.625 ;
        RECT 45.480 21.655 51.690 21.825 ;
        RECT 56.600 21.825 56.930 22.625 ;
        RECT 57.440 21.825 57.770 22.625 ;
        RECT 58.280 21.825 58.610 22.625 ;
        RECT 59.120 21.825 59.450 22.625 ;
        RECT 59.960 21.825 60.290 22.625 ;
        RECT 60.800 21.825 61.130 22.625 ;
        RECT 61.640 21.825 61.970 22.625 ;
        RECT 62.480 21.825 62.810 22.625 ;
        RECT 56.600 21.655 62.810 21.825 ;
        RECT 65.610 21.825 65.940 22.625 ;
        RECT 66.450 21.825 66.780 22.625 ;
        RECT 67.290 21.825 67.620 22.625 ;
        RECT 68.130 21.825 68.460 22.625 ;
        RECT 68.970 21.825 69.300 22.625 ;
        RECT 69.810 21.825 70.140 22.625 ;
        RECT 70.650 21.825 70.980 22.625 ;
        RECT 71.490 21.825 71.820 22.625 ;
        RECT 65.610 21.655 71.820 21.825 ;
        RECT 74.620 21.825 74.950 22.625 ;
        RECT 75.460 21.825 75.790 22.625 ;
        RECT 76.300 21.825 76.630 22.625 ;
        RECT 77.140 21.825 77.470 22.625 ;
        RECT 77.980 21.825 78.310 22.625 ;
        RECT 78.820 21.825 79.150 22.625 ;
        RECT 79.660 21.825 79.990 22.625 ;
        RECT 80.500 21.825 80.830 22.625 ;
        RECT 74.620 21.655 80.830 21.825 ;
        RECT 85.740 21.825 86.070 22.625 ;
        RECT 86.580 21.825 86.910 22.625 ;
        RECT 87.420 21.825 87.750 22.625 ;
        RECT 88.260 21.825 88.590 22.625 ;
        RECT 89.100 21.825 89.430 22.625 ;
        RECT 89.940 21.825 90.270 22.625 ;
        RECT 90.780 21.825 91.110 22.625 ;
        RECT 91.620 21.825 91.950 22.625 ;
        RECT 85.740 21.655 91.950 21.825 ;
        RECT 42.350 21.065 42.680 21.655 ;
        RECT 44.985 21.235 50.425 21.475 ;
        RECT 51.360 21.065 51.690 21.655 ;
        RECT 56.105 21.235 61.545 21.475 ;
        RECT 62.480 21.065 62.810 21.655 ;
        RECT 65.115 21.235 70.555 21.475 ;
        RECT 71.490 21.065 71.820 21.655 ;
        RECT 74.125 21.235 79.565 21.475 ;
        RECT 80.500 21.065 80.830 21.655 ;
        RECT 85.245 21.235 90.685 21.475 ;
        RECT 91.620 21.065 91.950 21.655 ;
        RECT 36.470 20.875 42.680 21.065 ;
        RECT 36.470 20.415 36.800 20.875 ;
        RECT 37.310 20.415 37.640 20.875 ;
        RECT 38.150 20.415 38.480 20.875 ;
        RECT 38.990 20.415 39.320 20.875 ;
        RECT 39.830 20.415 40.160 20.875 ;
        RECT 40.670 20.415 41.000 20.875 ;
        RECT 41.510 20.415 41.840 20.875 ;
        RECT 42.350 20.415 42.680 20.875 ;
        RECT 45.480 20.875 51.690 21.065 ;
        RECT 45.480 20.415 45.810 20.875 ;
        RECT 46.320 20.415 46.650 20.875 ;
        RECT 47.160 20.415 47.490 20.875 ;
        RECT 48.000 20.415 48.330 20.875 ;
        RECT 48.840 20.415 49.170 20.875 ;
        RECT 49.680 20.415 50.010 20.875 ;
        RECT 50.520 20.415 50.850 20.875 ;
        RECT 51.360 20.415 51.690 20.875 ;
        RECT 56.600 20.875 62.810 21.065 ;
        RECT 56.600 20.415 56.930 20.875 ;
        RECT 57.440 20.415 57.770 20.875 ;
        RECT 58.280 20.415 58.610 20.875 ;
        RECT 59.120 20.415 59.450 20.875 ;
        RECT 59.960 20.415 60.290 20.875 ;
        RECT 60.800 20.415 61.130 20.875 ;
        RECT 61.640 20.415 61.970 20.875 ;
        RECT 62.480 20.415 62.810 20.875 ;
        RECT 65.610 20.875 71.820 21.065 ;
        RECT 65.610 20.415 65.940 20.875 ;
        RECT 66.450 20.415 66.780 20.875 ;
        RECT 67.290 20.415 67.620 20.875 ;
        RECT 68.130 20.415 68.460 20.875 ;
        RECT 68.970 20.415 69.300 20.875 ;
        RECT 69.810 20.415 70.140 20.875 ;
        RECT 70.650 20.415 70.980 20.875 ;
        RECT 71.490 20.415 71.820 20.875 ;
        RECT 74.620 20.875 80.830 21.065 ;
        RECT 74.620 20.415 74.950 20.875 ;
        RECT 75.460 20.415 75.790 20.875 ;
        RECT 76.300 20.415 76.630 20.875 ;
        RECT 77.140 20.415 77.470 20.875 ;
        RECT 77.980 20.415 78.310 20.875 ;
        RECT 78.820 20.415 79.150 20.875 ;
        RECT 79.660 20.415 79.990 20.875 ;
        RECT 80.500 20.415 80.830 20.875 ;
        RECT 85.740 20.875 91.950 21.065 ;
        RECT 85.740 20.415 86.070 20.875 ;
        RECT 86.580 20.415 86.910 20.875 ;
        RECT 87.420 20.415 87.750 20.875 ;
        RECT 88.260 20.415 88.590 20.875 ;
        RECT 89.100 20.415 89.430 20.875 ;
        RECT 89.940 20.415 90.270 20.875 ;
        RECT 90.780 20.415 91.110 20.875 ;
        RECT 91.620 20.415 91.950 20.875 ;
        RECT 36.470 17.225 36.800 18.025 ;
        RECT 37.310 17.225 37.640 18.025 ;
        RECT 38.150 17.225 38.480 18.025 ;
        RECT 38.990 17.225 39.320 18.025 ;
        RECT 39.830 17.225 40.160 18.025 ;
        RECT 40.670 17.225 41.000 18.025 ;
        RECT 41.510 17.225 41.840 18.025 ;
        RECT 42.350 17.225 42.680 18.025 ;
        RECT 36.470 17.055 42.680 17.225 ;
        RECT 45.480 17.225 45.810 18.025 ;
        RECT 46.320 17.225 46.650 18.025 ;
        RECT 47.160 17.225 47.490 18.025 ;
        RECT 48.000 17.225 48.330 18.025 ;
        RECT 48.840 17.225 49.170 18.025 ;
        RECT 49.680 17.225 50.010 18.025 ;
        RECT 50.520 17.225 50.850 18.025 ;
        RECT 51.360 17.225 51.690 18.025 ;
        RECT 45.480 17.055 51.690 17.225 ;
        RECT 56.600 17.225 56.930 18.025 ;
        RECT 57.440 17.225 57.770 18.025 ;
        RECT 58.280 17.225 58.610 18.025 ;
        RECT 59.120 17.225 59.450 18.025 ;
        RECT 59.960 17.225 60.290 18.025 ;
        RECT 60.800 17.225 61.130 18.025 ;
        RECT 61.640 17.225 61.970 18.025 ;
        RECT 62.480 17.225 62.810 18.025 ;
        RECT 56.600 17.055 62.810 17.225 ;
        RECT 65.610 17.225 65.940 18.025 ;
        RECT 66.450 17.225 66.780 18.025 ;
        RECT 67.290 17.225 67.620 18.025 ;
        RECT 68.130 17.225 68.460 18.025 ;
        RECT 68.970 17.225 69.300 18.025 ;
        RECT 69.810 17.225 70.140 18.025 ;
        RECT 70.650 17.225 70.980 18.025 ;
        RECT 71.490 17.225 71.820 18.025 ;
        RECT 65.610 17.055 71.820 17.225 ;
        RECT 74.620 17.225 74.950 18.025 ;
        RECT 75.460 17.225 75.790 18.025 ;
        RECT 76.300 17.225 76.630 18.025 ;
        RECT 77.140 17.225 77.470 18.025 ;
        RECT 77.980 17.225 78.310 18.025 ;
        RECT 78.820 17.225 79.150 18.025 ;
        RECT 79.660 17.225 79.990 18.025 ;
        RECT 80.500 17.225 80.830 18.025 ;
        RECT 74.620 17.055 80.830 17.225 ;
        RECT 42.350 16.465 42.680 17.055 ;
        RECT 44.985 16.635 50.425 16.875 ;
        RECT 51.360 16.465 51.690 17.055 ;
        RECT 56.105 16.635 61.545 16.875 ;
        RECT 62.480 16.465 62.810 17.055 ;
        RECT 65.115 16.635 70.555 16.875 ;
        RECT 71.490 16.465 71.820 17.055 ;
        RECT 74.125 16.635 79.565 16.875 ;
        RECT 80.500 16.465 80.830 17.055 ;
        RECT 36.470 16.275 42.680 16.465 ;
        RECT 36.470 15.815 36.800 16.275 ;
        RECT 37.310 15.815 37.640 16.275 ;
        RECT 38.150 15.815 38.480 16.275 ;
        RECT 38.990 15.815 39.320 16.275 ;
        RECT 39.830 15.815 40.160 16.275 ;
        RECT 40.670 15.815 41.000 16.275 ;
        RECT 41.510 15.815 41.840 16.275 ;
        RECT 42.350 15.815 42.680 16.275 ;
        RECT 45.480 16.275 51.690 16.465 ;
        RECT 45.480 15.815 45.810 16.275 ;
        RECT 46.320 15.815 46.650 16.275 ;
        RECT 47.160 15.815 47.490 16.275 ;
        RECT 48.000 15.815 48.330 16.275 ;
        RECT 48.840 15.815 49.170 16.275 ;
        RECT 49.680 15.815 50.010 16.275 ;
        RECT 50.520 15.815 50.850 16.275 ;
        RECT 51.360 15.815 51.690 16.275 ;
        RECT 56.600 16.275 62.810 16.465 ;
        RECT 56.600 15.815 56.930 16.275 ;
        RECT 57.440 15.815 57.770 16.275 ;
        RECT 58.280 15.815 58.610 16.275 ;
        RECT 59.120 15.815 59.450 16.275 ;
        RECT 59.960 15.815 60.290 16.275 ;
        RECT 60.800 15.815 61.130 16.275 ;
        RECT 61.640 15.815 61.970 16.275 ;
        RECT 62.480 15.815 62.810 16.275 ;
        RECT 65.610 16.275 71.820 16.465 ;
        RECT 65.610 15.815 65.940 16.275 ;
        RECT 66.450 15.815 66.780 16.275 ;
        RECT 67.290 15.815 67.620 16.275 ;
        RECT 68.130 15.815 68.460 16.275 ;
        RECT 68.970 15.815 69.300 16.275 ;
        RECT 69.810 15.815 70.140 16.275 ;
        RECT 70.650 15.815 70.980 16.275 ;
        RECT 71.490 15.815 71.820 16.275 ;
        RECT 74.620 16.275 80.830 16.465 ;
        RECT 74.620 15.815 74.950 16.275 ;
        RECT 75.460 15.815 75.790 16.275 ;
        RECT 76.300 15.815 76.630 16.275 ;
        RECT 77.140 15.815 77.470 16.275 ;
        RECT 77.980 15.815 78.310 16.275 ;
        RECT 78.820 15.815 79.150 16.275 ;
        RECT 79.660 15.815 79.990 16.275 ;
        RECT 80.500 15.815 80.830 16.275 ;
      LAYER met1 ;
        RECT 102.545 168.110 102.955 168.140 ;
        RECT 119.510 168.110 119.920 168.140 ;
        RECT 102.545 167.760 119.920 168.110 ;
        RECT 102.545 167.730 102.955 167.760 ;
        RECT 119.510 167.730 119.920 167.760 ;
        RECT 120.765 164.940 122.165 165.040 ;
        RECT 130.565 164.940 131.195 164.970 ;
        RECT 115.430 164.935 131.195 164.940 ;
        RECT 115.150 164.370 131.195 164.935 ;
        RECT 115.150 164.365 118.480 164.370 ;
        RECT 115.150 164.360 118.475 164.365 ;
        RECT 115.150 164.355 118.470 164.360 ;
        RECT 115.150 164.350 118.465 164.355 ;
        RECT 115.150 164.345 118.460 164.350 ;
        RECT 120.765 164.340 122.165 164.370 ;
        RECT 130.565 164.340 131.195 164.370 ;
        RECT 119.540 164.195 119.890 164.225 ;
        RECT 116.245 163.940 119.890 164.195 ;
        RECT 119.540 163.850 119.890 163.940 ;
        RECT 121.465 163.640 122.165 164.340 ;
        RECT 121.465 158.480 122.165 159.180 ;
        RECT 120.765 158.380 122.165 158.480 ;
        RECT 115.430 158.375 122.165 158.380 ;
        RECT 115.150 157.810 122.165 158.375 ;
        RECT 115.150 157.805 118.480 157.810 ;
        RECT 115.150 157.800 118.475 157.805 ;
        RECT 115.150 157.795 118.470 157.800 ;
        RECT 115.150 157.790 118.465 157.795 ;
        RECT 115.150 157.785 118.460 157.790 ;
        RECT 120.765 157.780 122.165 157.810 ;
        RECT 119.540 157.635 119.890 157.665 ;
        RECT 116.245 157.380 119.890 157.635 ;
        RECT 119.540 157.315 119.890 157.380 ;
        RECT 121.465 157.080 122.165 157.780 ;
        RECT 88.825 151.855 89.175 151.885 ;
        RECT 96.295 151.855 96.585 152.315 ;
        RECT 121.465 151.920 122.165 152.620 ;
        RECT 102.605 151.855 102.955 151.885 ;
        RECT 88.825 151.565 92.000 151.855 ;
        RECT 96.295 151.565 102.955 151.855 ;
        RECT 120.765 151.820 122.165 151.920 ;
        RECT 115.430 151.815 122.165 151.820 ;
        RECT 88.825 151.535 89.175 151.565 ;
        RECT 96.295 151.090 96.585 151.565 ;
        RECT 102.605 151.535 102.955 151.565 ;
        RECT 115.150 151.250 122.165 151.815 ;
        RECT 115.150 151.245 118.480 151.250 ;
        RECT 115.150 151.240 118.475 151.245 ;
        RECT 115.150 151.235 118.470 151.240 ;
        RECT 115.150 151.230 118.465 151.235 ;
        RECT 115.150 151.225 118.460 151.230 ;
        RECT 120.765 151.220 122.165 151.250 ;
        RECT 119.540 151.075 119.890 151.110 ;
        RECT 116.245 150.820 119.890 151.075 ;
        RECT 119.540 150.780 119.890 150.820 ;
        RECT 121.465 150.520 122.165 151.220 ;
        RECT 78.005 148.215 78.355 148.245 ;
        RECT 85.430 148.215 85.720 148.675 ;
        RECT 87.025 148.215 87.375 148.245 ;
        RECT 88.825 148.215 89.175 148.245 ;
        RECT 96.295 148.215 96.585 148.675 ;
        RECT 102.605 148.215 102.955 148.245 ;
        RECT 78.005 147.925 81.180 148.215 ;
        RECT 85.430 147.925 91.975 148.215 ;
        RECT 96.295 147.925 102.955 148.215 ;
        RECT 78.005 147.895 78.355 147.925 ;
        RECT 85.430 147.450 85.720 147.925 ;
        RECT 87.025 147.895 87.375 147.925 ;
        RECT 88.825 147.895 89.175 147.925 ;
        RECT 96.295 147.450 96.585 147.925 ;
        RECT 102.605 147.895 102.955 147.925 ;
        RECT 121.465 145.360 122.165 146.060 ;
        RECT 120.765 145.260 122.165 145.360 ;
        RECT 115.430 145.255 122.165 145.260 ;
        RECT 33.550 144.255 34.465 144.605 ;
        RECT 46.600 144.580 46.890 144.905 ;
        RECT 52.395 144.580 52.685 144.905 ;
        RECT 35.345 144.285 36.175 144.575 ;
        RECT 36.345 144.285 39.180 144.575 ;
        RECT 39.435 144.285 42.005 144.575 ;
        RECT 42.250 144.285 45.510 144.575 ;
        RECT 33.150 143.985 33.845 144.110 ;
        RECT 35.345 143.985 35.635 144.285 ;
        RECT 33.150 143.665 35.635 143.985 ;
        RECT 46.600 144.280 50.885 144.580 ;
        RECT 52.395 144.280 56.680 144.580 ;
        RECT 60.025 144.525 60.315 144.905 ;
        RECT 62.795 144.525 63.155 144.610 ;
        RECT 76.420 144.575 76.710 145.035 ;
        RECT 78.005 144.575 78.355 144.605 ;
        RECT 85.475 144.575 85.765 145.035 ;
        RECT 87.025 144.575 87.375 144.605 ;
        RECT 70.000 144.525 72.175 144.575 ;
        RECT 60.025 144.385 72.175 144.525 ;
        RECT 46.600 143.945 46.890 144.280 ;
        RECT 52.395 143.945 52.685 144.280 ;
        RECT 60.025 143.945 60.315 144.385 ;
        RECT 62.795 144.250 63.155 144.385 ;
        RECT 70.000 144.285 72.175 144.385 ;
        RECT 76.420 144.285 81.260 144.575 ;
        RECT 85.475 144.285 87.375 144.575 ;
        RECT 76.420 143.810 76.710 144.285 ;
        RECT 78.005 144.255 78.355 144.285 ;
        RECT 85.475 143.810 85.765 144.285 ;
        RECT 87.025 144.255 87.375 144.285 ;
        RECT 88.825 144.575 89.175 144.605 ;
        RECT 96.295 144.575 96.585 145.035 ;
        RECT 115.150 144.690 122.165 145.255 ;
        RECT 115.150 144.685 118.480 144.690 ;
        RECT 115.150 144.680 118.475 144.685 ;
        RECT 115.150 144.675 118.470 144.680 ;
        RECT 115.150 144.670 118.465 144.675 ;
        RECT 115.150 144.665 118.460 144.670 ;
        RECT 120.765 144.660 122.165 144.690 ;
        RECT 102.605 144.575 102.955 144.605 ;
        RECT 88.825 144.285 92.000 144.575 ;
        RECT 96.295 144.285 102.955 144.575 ;
        RECT 119.540 144.515 119.890 144.550 ;
        RECT 88.825 144.245 89.175 144.285 ;
        RECT 96.295 143.810 96.585 144.285 ;
        RECT 102.605 144.255 102.955 144.285 ;
        RECT 116.245 144.260 119.890 144.515 ;
        RECT 119.540 144.220 119.890 144.260 ;
        RECT 35.345 143.660 35.635 143.665 ;
        RECT 34.115 142.520 34.435 142.550 ;
        RECT 62.115 142.520 62.435 142.550 ;
        RECT 34.115 142.380 62.435 142.520 ;
        RECT 34.115 142.230 34.435 142.380 ;
        RECT 62.115 142.230 62.435 142.380 ;
        RECT 34.115 140.980 34.435 141.130 ;
        RECT 62.835 140.980 63.155 141.130 ;
        RECT 34.115 140.840 63.155 140.980 ;
        RECT 34.115 140.810 34.435 140.840 ;
        RECT 62.835 140.810 63.155 140.840 ;
        RECT 30.125 137.840 32.925 138.130 ;
        RECT 33.550 137.810 34.465 138.160 ;
        RECT 46.595 138.135 46.885 138.460 ;
        RECT 52.385 138.135 52.675 138.460 ;
        RECT 35.345 137.840 36.175 138.130 ;
        RECT 36.340 137.840 39.200 138.130 ;
        RECT 39.430 137.840 42.000 138.130 ;
        RECT 42.245 137.840 45.505 138.130 ;
        RECT 33.150 137.540 33.845 137.665 ;
        RECT 35.345 137.540 35.635 137.840 ;
        RECT 33.150 137.220 35.635 137.540 ;
        RECT 46.595 137.835 50.880 138.135 ;
        RECT 52.385 137.835 56.670 138.135 ;
        RECT 60.015 138.060 60.305 138.460 ;
        RECT 62.075 138.060 62.435 138.165 ;
        RECT 69.960 138.060 72.190 138.165 ;
        RECT 60.015 137.920 72.190 138.060 ;
        RECT 46.595 137.500 46.885 137.835 ;
        RECT 52.385 137.500 52.675 137.835 ;
        RECT 60.015 137.500 60.305 137.920 ;
        RECT 62.075 137.805 62.435 137.920 ;
        RECT 69.960 137.805 72.190 137.920 ;
        RECT 76.420 138.130 76.710 138.590 ;
        RECT 78.005 138.130 78.355 138.160 ;
        RECT 85.475 138.130 85.765 138.590 ;
        RECT 87.025 138.130 87.375 138.160 ;
        RECT 76.420 137.840 81.260 138.130 ;
        RECT 85.475 137.840 87.375 138.130 ;
        RECT 76.420 137.365 76.710 137.840 ;
        RECT 78.005 137.810 78.355 137.840 ;
        RECT 85.475 137.365 85.765 137.840 ;
        RECT 87.025 137.810 87.375 137.840 ;
        RECT 88.825 138.130 89.175 138.160 ;
        RECT 96.295 138.130 96.585 138.590 ;
        RECT 120.765 138.320 122.165 138.420 ;
        RECT 115.430 138.315 122.165 138.320 ;
        RECT 102.545 138.130 102.895 138.160 ;
        RECT 88.825 137.840 92.000 138.130 ;
        RECT 96.295 137.840 102.895 138.130 ;
        RECT 88.825 137.810 89.175 137.840 ;
        RECT 96.295 137.365 96.585 137.840 ;
        RECT 102.545 137.810 102.895 137.840 ;
        RECT 115.150 137.750 122.165 138.315 ;
        RECT 115.150 137.745 118.480 137.750 ;
        RECT 115.150 137.740 118.475 137.745 ;
        RECT 115.150 137.735 118.470 137.740 ;
        RECT 115.150 137.730 118.465 137.735 ;
        RECT 115.150 137.725 118.460 137.730 ;
        RECT 120.765 137.720 122.165 137.750 ;
        RECT 119.540 137.575 119.890 137.610 ;
        RECT 116.245 137.320 119.890 137.575 ;
        RECT 119.540 137.295 119.890 137.320 ;
        RECT 35.345 137.215 35.635 137.220 ;
        RECT 121.465 137.020 122.165 137.720 ;
        RECT 78.005 134.490 78.355 134.520 ;
        RECT 85.430 134.490 85.720 134.950 ;
        RECT 87.025 134.490 87.375 134.520 ;
        RECT 88.825 134.490 89.175 134.520 ;
        RECT 96.295 134.490 96.585 134.950 ;
        RECT 102.545 134.490 102.895 134.520 ;
        RECT 78.005 134.200 81.180 134.490 ;
        RECT 85.430 134.200 92.000 134.490 ;
        RECT 96.295 134.200 102.895 134.490 ;
        RECT 78.005 134.170 78.355 134.200 ;
        RECT 85.430 133.725 85.720 134.200 ;
        RECT 87.025 134.170 87.375 134.200 ;
        RECT 88.825 134.170 89.175 134.200 ;
        RECT 96.295 133.725 96.585 134.200 ;
        RECT 102.545 134.170 102.895 134.200 ;
        RECT 121.465 131.860 122.165 132.560 ;
        RECT 120.765 131.760 122.165 131.860 ;
        RECT 115.430 131.755 122.165 131.760 ;
        RECT 88.825 130.840 89.175 130.870 ;
        RECT 96.295 130.840 96.585 131.300 ;
        RECT 115.150 131.190 122.165 131.755 ;
        RECT 115.150 131.185 118.480 131.190 ;
        RECT 115.150 131.180 118.475 131.185 ;
        RECT 115.150 131.175 118.470 131.180 ;
        RECT 115.150 131.170 118.465 131.175 ;
        RECT 115.150 131.165 118.460 131.170 ;
        RECT 120.765 131.160 122.165 131.190 ;
        RECT 119.510 131.015 119.920 131.050 ;
        RECT 102.545 130.840 102.895 130.870 ;
        RECT 88.825 130.550 92.000 130.840 ;
        RECT 96.295 130.550 102.895 130.840 ;
        RECT 116.670 130.760 119.920 131.015 ;
        RECT 119.510 130.635 119.920 130.760 ;
        RECT 88.825 130.520 89.175 130.550 ;
        RECT 96.295 130.075 96.585 130.550 ;
        RECT 102.545 130.520 102.895 130.550 ;
        RECT 121.465 130.460 122.165 131.160 ;
        RECT 121.465 125.300 122.165 126.000 ;
        RECT 120.765 125.200 122.165 125.300 ;
        RECT 115.430 125.195 122.165 125.200 ;
        RECT 115.150 124.630 122.165 125.195 ;
        RECT 115.150 124.625 118.480 124.630 ;
        RECT 115.150 124.620 118.475 124.625 ;
        RECT 115.150 124.615 118.470 124.620 ;
        RECT 115.150 124.610 118.465 124.615 ;
        RECT 115.150 124.605 118.460 124.610 ;
        RECT 120.765 124.600 122.165 124.630 ;
        RECT 119.510 124.455 119.920 124.490 ;
        RECT 116.670 124.200 119.920 124.455 ;
        RECT 119.510 124.075 119.920 124.200 ;
        RECT 121.465 123.900 122.165 124.600 ;
        RECT 121.465 118.740 122.165 119.440 ;
        RECT 120.765 118.640 122.165 118.740 ;
        RECT 115.430 118.635 122.165 118.640 ;
        RECT 115.150 118.070 122.165 118.635 ;
        RECT 115.150 118.065 118.480 118.070 ;
        RECT 115.150 118.060 118.475 118.065 ;
        RECT 115.150 118.055 118.470 118.060 ;
        RECT 115.150 118.050 118.465 118.055 ;
        RECT 115.150 118.045 118.460 118.050 ;
        RECT 120.765 118.040 122.165 118.070 ;
        RECT 119.510 117.895 119.920 117.930 ;
        RECT 116.670 117.640 119.920 117.895 ;
        RECT 119.510 117.515 119.920 117.640 ;
        RECT 121.465 117.340 122.165 118.040 ;
        RECT 102.545 114.160 102.955 114.190 ;
        RECT 119.510 114.160 119.920 114.190 ;
        RECT 102.545 113.810 119.920 114.160 ;
        RECT 102.545 113.780 102.955 113.810 ;
        RECT 119.510 113.780 119.920 113.810 ;
        RECT 105.280 46.740 105.620 46.750 ;
        RECT 94.500 46.390 100.400 46.470 ;
        RECT 105.050 46.460 105.620 46.740 ;
        RECT 121.860 46.510 122.200 46.780 ;
        RECT 94.500 46.050 100.420 46.390 ;
        RECT 94.500 45.970 100.400 46.050 ;
        RECT 94.500 45.410 95.000 45.970 ;
        RECT 105.000 45.960 117.150 46.460 ;
        RECT 121.860 46.010 124.980 46.510 ;
        RECT 105.050 45.670 105.620 45.960 ;
        RECT 105.250 45.590 105.620 45.670 ;
        RECT 121.860 45.600 122.200 46.010 ;
        RECT 105.250 45.580 105.550 45.590 ;
        RECT 124.480 45.500 124.980 46.010 ;
        RECT 94.460 44.430 94.960 44.880 ;
        RECT 124.450 44.430 124.950 44.930 ;
        RECT 94.445 43.860 125.005 44.430 ;
        RECT 42.415 32.240 42.705 32.680 ;
        RECT 43.330 32.240 44.010 32.270 ;
        RECT 42.415 31.950 44.010 32.240 ;
        RECT 42.415 31.500 42.705 31.950 ;
        RECT 43.330 31.920 44.010 31.950 ;
        RECT 43.670 31.570 44.010 31.920 ;
        RECT 28.195 28.650 28.875 28.680 ;
        RECT 34.320 28.650 35.340 28.680 ;
        RECT 42.415 28.650 42.705 29.100 ;
        RECT 43.330 28.650 44.350 28.680 ;
        RECT 28.195 28.370 38.105 28.650 ;
        RECT 42.415 28.370 47.115 28.650 ;
        RECT 28.195 28.340 28.875 28.370 ;
        RECT 34.320 28.340 35.340 28.370 ;
        RECT 28.195 28.000 28.535 28.340 ;
        RECT 34.660 28.000 35.000 28.340 ;
        RECT 42.415 27.920 42.705 28.370 ;
        RECT 43.330 28.340 44.350 28.370 ;
        RECT 34.660 25.100 35.000 25.440 ;
        RECT 34.660 25.070 35.340 25.100 ;
        RECT 42.415 25.070 42.705 25.505 ;
        RECT 43.335 25.070 44.355 25.100 ;
        RECT 51.945 25.070 52.285 25.100 ;
        RECT 55.245 25.070 56.265 25.100 ;
        RECT 64.255 25.070 65.275 25.100 ;
        RECT 72.925 25.070 73.945 25.100 ;
        RECT 34.660 24.790 38.105 25.070 ;
        RECT 42.415 24.790 73.945 25.070 ;
        RECT 34.660 24.760 35.340 24.790 ;
        RECT 42.415 24.340 42.705 24.790 ;
        RECT 43.335 24.760 44.355 24.790 ;
        RECT 51.945 24.760 52.285 24.790 ;
        RECT 55.245 24.760 56.265 24.790 ;
        RECT 64.255 24.760 65.275 24.790 ;
        RECT 72.925 24.760 73.945 24.790 ;
        RECT 42.415 21.490 42.705 21.925 ;
        RECT 43.335 21.490 44.355 21.520 ;
        RECT 51.425 21.490 51.715 21.935 ;
        RECT 52.015 21.490 52.695 21.520 ;
        RECT 42.415 21.210 47.115 21.490 ;
        RECT 51.425 21.210 52.695 21.490 ;
        RECT 42.415 20.765 42.705 21.210 ;
        RECT 43.335 21.180 44.355 21.210 ;
        RECT 51.425 20.765 51.715 21.210 ;
        RECT 52.015 21.180 52.695 21.210 ;
        RECT 55.585 21.490 55.925 22.200 ;
        RECT 62.545 21.490 62.835 21.935 ;
        RECT 63.140 21.490 63.820 21.520 ;
        RECT 55.585 21.210 58.235 21.490 ;
        RECT 62.545 21.210 63.820 21.490 ;
        RECT 55.585 21.180 55.925 21.210 ;
        RECT 52.355 20.840 52.695 21.180 ;
        RECT 62.545 20.765 62.835 21.210 ;
        RECT 63.140 21.180 63.820 21.210 ;
        RECT 64.595 21.490 64.935 22.200 ;
        RECT 71.555 21.490 71.845 21.935 ;
        RECT 72.145 21.490 72.825 21.520 ;
        RECT 64.595 21.210 67.245 21.490 ;
        RECT 71.555 21.210 72.825 21.490 ;
        RECT 64.595 21.180 64.935 21.210 ;
        RECT 63.480 20.840 63.820 21.180 ;
        RECT 71.555 20.765 71.845 21.210 ;
        RECT 72.145 21.180 72.825 21.210 ;
        RECT 73.605 21.500 73.945 22.210 ;
        RECT 73.605 21.220 76.255 21.500 ;
        RECT 80.565 21.490 80.855 21.935 ;
        RECT 81.155 21.490 81.835 21.520 ;
        RECT 73.605 21.190 73.945 21.220 ;
        RECT 80.565 21.210 81.835 21.490 ;
        RECT 72.485 20.840 72.825 21.180 ;
        RECT 80.565 20.765 80.855 21.210 ;
        RECT 81.155 21.180 81.835 21.210 ;
        RECT 81.495 20.840 81.835 21.180 ;
        RECT 84.725 21.490 85.065 21.520 ;
        RECT 91.685 21.490 91.975 21.935 ;
        RECT 92.275 21.490 92.955 21.520 ;
        RECT 84.725 21.210 87.375 21.490 ;
        RECT 91.685 21.210 92.955 21.490 ;
        RECT 84.725 20.540 85.065 21.210 ;
        RECT 91.685 20.765 91.975 21.210 ;
        RECT 92.275 21.180 92.955 21.210 ;
        RECT 92.615 20.840 92.955 21.180 ;
        RECT 63.480 19.390 63.820 19.730 ;
        RECT 72.485 19.390 72.825 19.730 ;
        RECT 81.495 19.390 81.835 19.730 ;
        RECT 92.615 19.390 92.955 19.730 ;
        RECT 44.465 19.360 45.485 19.390 ;
        RECT 52.015 19.360 53.035 19.390 ;
        RECT 55.245 19.360 56.265 19.390 ;
        RECT 63.140 19.360 63.820 19.390 ;
        RECT 64.255 19.360 65.275 19.385 ;
        RECT 72.145 19.360 72.825 19.390 ;
        RECT 73.265 19.360 74.285 19.390 ;
        RECT 81.155 19.360 81.835 19.390 ;
        RECT 84.385 19.360 85.405 19.390 ;
        RECT 92.275 19.360 92.955 19.390 ;
        RECT 44.465 19.080 92.955 19.360 ;
        RECT 44.465 19.050 45.485 19.080 ;
        RECT 52.015 19.050 53.035 19.080 ;
        RECT 55.245 19.050 56.265 19.080 ;
        RECT 63.140 19.050 63.820 19.080 ;
        RECT 64.255 19.045 65.275 19.080 ;
        RECT 72.145 19.050 72.825 19.080 ;
        RECT 73.265 19.050 74.285 19.080 ;
        RECT 81.155 19.050 81.835 19.080 ;
        RECT 84.385 19.050 85.405 19.080 ;
        RECT 92.275 19.050 92.955 19.080 ;
        RECT 42.415 16.890 42.705 17.335 ;
        RECT 43.005 16.890 43.685 16.920 ;
        RECT 42.415 16.610 43.685 16.890 ;
        RECT 42.415 16.165 42.705 16.610 ;
        RECT 43.005 16.580 43.685 16.610 ;
        RECT 44.465 16.890 44.805 17.600 ;
        RECT 51.425 16.890 51.715 17.335 ;
        RECT 52.015 16.890 52.695 16.920 ;
        RECT 44.465 16.610 47.115 16.890 ;
        RECT 51.425 16.610 52.695 16.890 ;
        RECT 44.465 16.580 44.805 16.610 ;
        RECT 43.345 16.240 43.685 16.580 ;
        RECT 51.425 16.165 51.715 16.610 ;
        RECT 52.015 16.580 52.695 16.610 ;
        RECT 55.585 16.890 55.925 17.600 ;
        RECT 62.545 16.890 62.835 17.335 ;
        RECT 63.135 16.890 63.815 16.920 ;
        RECT 55.585 16.610 58.235 16.890 ;
        RECT 62.545 16.610 63.815 16.890 ;
        RECT 55.585 16.580 55.925 16.610 ;
        RECT 52.355 16.240 52.695 16.580 ;
        RECT 62.545 16.165 62.835 16.610 ;
        RECT 63.135 16.580 63.815 16.610 ;
        RECT 64.595 16.890 64.935 17.600 ;
        RECT 71.555 16.890 71.845 17.335 ;
        RECT 72.145 16.890 72.825 16.920 ;
        RECT 64.595 16.610 67.245 16.890 ;
        RECT 71.555 16.610 72.825 16.890 ;
        RECT 64.595 16.580 64.935 16.610 ;
        RECT 63.475 16.240 63.815 16.580 ;
        RECT 71.555 16.165 71.845 16.610 ;
        RECT 72.145 16.580 72.825 16.610 ;
        RECT 73.605 16.895 73.945 17.605 ;
        RECT 73.605 16.615 76.255 16.895 ;
        RECT 80.565 16.890 80.855 17.335 ;
        RECT 81.155 16.890 81.835 16.920 ;
        RECT 73.605 16.585 73.945 16.615 ;
        RECT 80.565 16.610 81.835 16.890 ;
        RECT 72.485 16.240 72.825 16.580 ;
        RECT 80.565 16.165 80.855 16.610 ;
        RECT 81.155 16.580 81.835 16.610 ;
        RECT 81.495 16.240 81.835 16.580 ;
        RECT 28.195 14.790 28.535 15.130 ;
        RECT 43.345 14.790 43.685 15.130 ;
        RECT 81.495 14.790 81.835 15.130 ;
        RECT 28.195 14.760 28.875 14.790 ;
        RECT 43.345 14.760 44.025 14.790 ;
        RECT 52.015 14.760 53.035 14.790 ;
        RECT 63.135 14.760 64.155 14.790 ;
        RECT 72.145 14.760 73.165 14.790 ;
        RECT 81.155 14.760 81.835 14.790 ;
        RECT 28.195 14.480 81.835 14.760 ;
        RECT 28.195 14.450 28.875 14.480 ;
        RECT 43.345 14.450 44.025 14.480 ;
        RECT 52.015 14.450 53.035 14.480 ;
        RECT 63.135 14.450 64.155 14.480 ;
        RECT 72.145 14.450 73.165 14.480 ;
        RECT 81.155 14.450 81.835 14.480 ;
      LAYER met2 ;
        RECT 102.545 167.730 102.955 168.140 ;
        RECT 119.510 167.730 119.920 168.140 ;
        RECT 102.635 151.885 102.925 167.730 ;
        RECT 88.825 151.535 89.175 151.885 ;
        RECT 102.605 151.535 102.955 151.885 ;
        RECT 88.855 148.245 89.145 151.535 ;
        RECT 102.635 148.245 102.925 151.535 ;
        RECT 78.005 147.895 78.355 148.245 ;
        RECT 87.025 147.895 87.375 148.245 ;
        RECT 88.825 147.895 89.175 148.245 ;
        RECT 102.605 147.895 102.955 148.245 ;
        RECT 34.115 144.255 34.465 144.575 ;
        RECT 34.145 142.550 34.285 144.255 ;
        RECT 62.795 144.250 63.155 144.610 ;
        RECT 78.035 144.605 78.325 147.895 ;
        RECT 87.055 144.605 87.345 147.895 ;
        RECT 88.855 144.605 89.145 147.895 ;
        RECT 102.635 144.605 102.925 147.895 ;
        RECT 78.005 144.255 78.355 144.605 ;
        RECT 87.025 144.255 87.375 144.605 ;
        RECT 34.115 142.230 34.435 142.550 ;
        RECT 62.115 142.230 62.435 142.550 ;
        RECT 34.115 140.810 34.435 141.130 ;
        RECT 34.145 138.160 34.285 140.810 ;
        RECT 62.265 138.165 62.405 142.230 ;
        RECT 62.985 141.130 63.125 144.250 ;
        RECT 88.825 144.245 89.175 144.605 ;
        RECT 102.605 144.255 102.955 144.605 ;
        RECT 119.540 144.220 119.890 167.730 ;
        RECT 120.765 164.340 122.165 165.040 ;
        RECT 130.565 164.340 131.195 164.970 ;
        RECT 121.465 158.480 122.165 164.340 ;
        RECT 120.765 157.780 122.165 158.480 ;
        RECT 121.465 151.920 122.165 157.780 ;
        RECT 120.765 151.220 122.165 151.920 ;
        RECT 121.465 145.360 122.165 151.220 ;
        RECT 120.765 144.660 122.165 145.360 ;
        RECT 62.835 140.810 63.155 141.130 ;
        RECT 34.115 137.810 34.465 138.160 ;
        RECT 62.075 137.805 62.435 138.165 ;
        RECT 78.005 137.810 78.355 138.160 ;
        RECT 87.025 137.810 87.375 138.160 ;
        RECT 88.825 137.810 89.175 138.160 ;
        RECT 102.545 137.810 102.895 138.160 ;
        RECT 78.035 134.520 78.325 137.810 ;
        RECT 87.055 134.520 87.345 137.810 ;
        RECT 88.855 134.520 89.145 137.810 ;
        RECT 102.575 134.520 102.865 137.810 ;
        RECT 120.765 137.720 122.165 138.420 ;
        RECT 78.005 134.170 78.355 134.520 ;
        RECT 87.025 134.170 87.375 134.520 ;
        RECT 88.825 134.170 89.175 134.520 ;
        RECT 102.545 134.170 102.895 134.520 ;
        RECT 88.855 130.870 89.145 134.170 ;
        RECT 102.575 130.870 102.865 134.170 ;
        RECT 119.540 131.050 119.890 137.610 ;
        RECT 121.465 131.860 122.165 137.720 ;
        RECT 120.765 131.160 122.165 131.860 ;
        RECT 88.825 130.520 89.175 130.870 ;
        RECT 102.545 130.520 102.895 130.870 ;
        RECT 119.510 130.635 119.920 131.050 ;
        RECT 102.575 114.190 102.865 130.520 ;
        RECT 119.540 124.490 119.890 130.635 ;
        RECT 121.465 125.300 122.165 131.160 ;
        RECT 120.765 124.600 122.165 125.300 ;
        RECT 119.510 124.075 119.920 124.490 ;
        RECT 119.540 117.930 119.890 124.075 ;
        RECT 121.465 118.740 122.165 124.600 ;
        RECT 120.765 118.040 122.165 118.740 ;
        RECT 119.510 117.515 119.920 117.930 ;
        RECT 119.540 114.190 119.890 117.515 ;
        RECT 102.545 113.780 102.955 114.190 ;
        RECT 119.510 113.780 119.920 114.190 ;
        RECT 121.465 91.550 122.165 118.040 ;
        RECT 120.330 90.850 122.165 91.550 ;
        RECT 120.330 84.630 120.930 90.850 ;
        RECT 120.320 84.030 120.930 84.630 ;
        RECT 120.330 79.100 120.930 84.030 ;
        RECT 110.650 55.600 112.000 56.100 ;
        RECT 110.650 55.050 111.170 55.600 ;
        RECT 94.495 45.970 95.575 46.495 ;
        RECT 110.670 46.460 111.170 55.050 ;
        RECT 94.495 44.350 94.990 45.970 ;
        RECT 110.260 45.960 111.640 46.460 ;
        RECT 123.745 46.025 124.950 46.515 ;
        RECT 94.495 43.855 95.675 44.350 ;
        RECT 112.990 43.815 115.000 44.420 ;
        RECT 124.460 44.365 124.950 46.025 ;
        RECT 123.835 43.875 124.950 44.365 ;
        RECT 124.460 43.860 124.950 43.875 ;
        RECT 113.750 42.295 114.355 43.815 ;
        RECT 113.745 40.485 114.355 42.295 ;
        RECT 113.745 39.875 115.015 40.485 ;
        RECT 113.745 39.865 114.355 39.875 ;
        RECT 43.330 31.920 44.010 32.270 ;
        RECT 43.670 31.570 44.010 31.920 ;
        RECT 43.700 28.680 43.980 31.570 ;
        RECT 28.195 28.340 28.875 28.680 ;
        RECT 34.320 28.340 35.340 28.680 ;
        RECT 43.330 28.340 44.350 28.680 ;
        RECT 28.195 28.000 28.535 28.340 ;
        RECT 34.660 28.000 35.000 28.340 ;
        RECT 28.225 15.130 28.505 28.000 ;
        RECT 34.690 25.440 34.970 28.000 ;
        RECT 34.660 25.100 35.000 25.440 ;
        RECT 34.660 24.760 35.340 25.100 ;
        RECT 43.335 24.760 44.355 25.100 ;
        RECT 51.945 24.760 52.285 25.100 ;
        RECT 55.245 24.760 56.265 25.100 ;
        RECT 64.255 24.760 65.275 25.100 ;
        RECT 72.925 24.760 73.945 25.100 ;
        RECT 43.705 21.520 43.985 24.760 ;
        RECT 55.615 22.200 55.895 24.760 ;
        RECT 64.625 22.200 64.905 24.760 ;
        RECT 73.635 22.210 73.915 24.760 ;
        RECT 43.335 21.180 44.355 21.520 ;
        RECT 52.015 21.180 52.695 21.520 ;
        RECT 55.585 21.180 55.925 22.200 ;
        RECT 63.140 21.180 63.820 21.520 ;
        RECT 64.595 21.180 64.935 22.200 ;
        RECT 72.145 21.180 72.825 21.520 ;
        RECT 73.605 21.190 73.945 22.210 ;
        RECT 81.155 21.180 81.835 21.520 ;
        RECT 52.355 20.840 52.695 21.180 ;
        RECT 63.480 20.840 63.820 21.180 ;
        RECT 72.485 20.840 72.825 21.180 ;
        RECT 81.495 20.840 81.835 21.180 ;
        RECT 52.385 19.390 52.665 20.840 ;
        RECT 63.510 19.730 63.790 20.840 ;
        RECT 72.515 19.730 72.795 20.840 ;
        RECT 81.525 19.730 81.805 20.840 ;
        RECT 84.725 20.540 85.065 21.520 ;
        RECT 92.275 21.180 92.955 21.520 ;
        RECT 92.615 20.840 92.955 21.180 ;
        RECT 63.480 19.390 63.820 19.730 ;
        RECT 72.485 19.390 72.825 19.730 ;
        RECT 81.495 19.390 81.835 19.730 ;
        RECT 84.755 19.390 85.035 20.540 ;
        RECT 92.645 19.730 92.925 20.840 ;
        RECT 92.615 19.390 92.955 19.730 ;
        RECT 44.465 19.050 45.485 19.390 ;
        RECT 52.015 19.050 53.035 19.390 ;
        RECT 55.245 19.050 56.265 19.390 ;
        RECT 63.140 19.050 63.820 19.390 ;
        RECT 44.495 17.600 44.775 19.050 ;
        RECT 55.615 17.600 55.895 19.050 ;
        RECT 64.255 19.045 65.275 19.385 ;
        RECT 72.145 19.050 72.825 19.390 ;
        RECT 73.265 19.050 74.285 19.390 ;
        RECT 81.155 19.050 81.835 19.390 ;
        RECT 84.385 19.050 85.405 19.390 ;
        RECT 92.275 19.050 92.955 19.390 ;
        RECT 64.625 17.600 64.905 19.045 ;
        RECT 73.635 17.605 73.915 19.050 ;
        RECT 43.005 16.580 43.685 16.920 ;
        RECT 44.465 16.580 44.805 17.600 ;
        RECT 52.015 16.580 52.695 16.920 ;
        RECT 55.585 16.580 55.925 17.600 ;
        RECT 63.135 16.580 63.815 16.920 ;
        RECT 64.595 16.580 64.935 17.600 ;
        RECT 72.145 16.580 72.825 16.920 ;
        RECT 73.605 16.585 73.945 17.605 ;
        RECT 81.155 16.580 81.835 16.920 ;
        RECT 43.345 16.240 43.685 16.580 ;
        RECT 52.355 16.240 52.695 16.580 ;
        RECT 63.475 16.240 63.815 16.580 ;
        RECT 72.485 16.240 72.825 16.580 ;
        RECT 81.495 16.240 81.835 16.580 ;
        RECT 43.375 15.130 43.655 16.240 ;
        RECT 28.195 14.790 28.535 15.130 ;
        RECT 43.345 14.790 43.685 15.130 ;
        RECT 52.385 14.790 52.665 16.240 ;
        RECT 63.505 14.790 63.785 16.240 ;
        RECT 72.515 14.790 72.795 16.240 ;
        RECT 81.525 15.130 81.805 16.240 ;
        RECT 81.495 14.790 81.835 15.130 ;
        RECT 28.195 14.450 28.875 14.790 ;
        RECT 43.345 14.450 44.025 14.790 ;
        RECT 52.015 14.450 53.035 14.790 ;
        RECT 63.135 14.450 64.155 14.790 ;
        RECT 72.145 14.450 73.165 14.790 ;
        RECT 81.155 14.450 81.835 14.790 ;
        RECT 120.860 13.615 121.465 17.250 ;
        RECT 130.595 13.615 131.165 164.340 ;
        RECT 120.860 13.045 131.165 13.615 ;
      LAYER met3 ;
        RECT 97.660 59.170 121.700 81.750 ;
        RECT 117.520 56.100 118.020 56.480 ;
        RECT 110.640 55.600 118.020 56.100 ;
        RECT 110.640 55.140 111.140 55.600 ;
        RECT 113.745 40.475 114.355 41.115 ;
        RECT 113.745 39.865 118.400 40.475 ;
        RECT 117.085 39.855 118.400 39.865 ;
        RECT 117.790 39.205 118.400 39.855 ;
        RECT 98.190 14.520 122.230 37.100 ;
      LAYER met4 ;
        RECT 98.055 59.565 119.845 81.355 ;
        RECT 117.500 56.050 118.000 59.565 ;
        RECT 121.200 59.230 121.680 81.690 ;
        RECT 117.010 55.550 118.000 56.050 ;
        RECT 117.085 39.855 118.400 40.465 ;
        RECT 117.790 36.705 118.400 39.855 ;
        RECT 98.585 14.915 120.375 36.705 ;
        RECT 121.730 14.580 122.210 37.040 ;
  END
END lvs_done (1)
END LIBRARY

